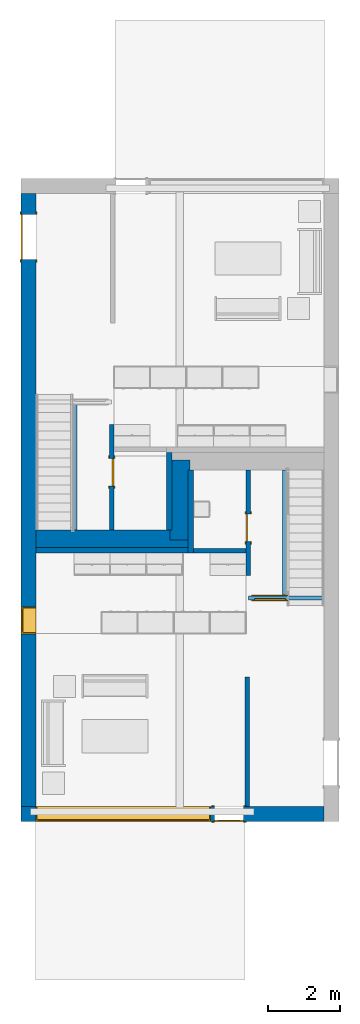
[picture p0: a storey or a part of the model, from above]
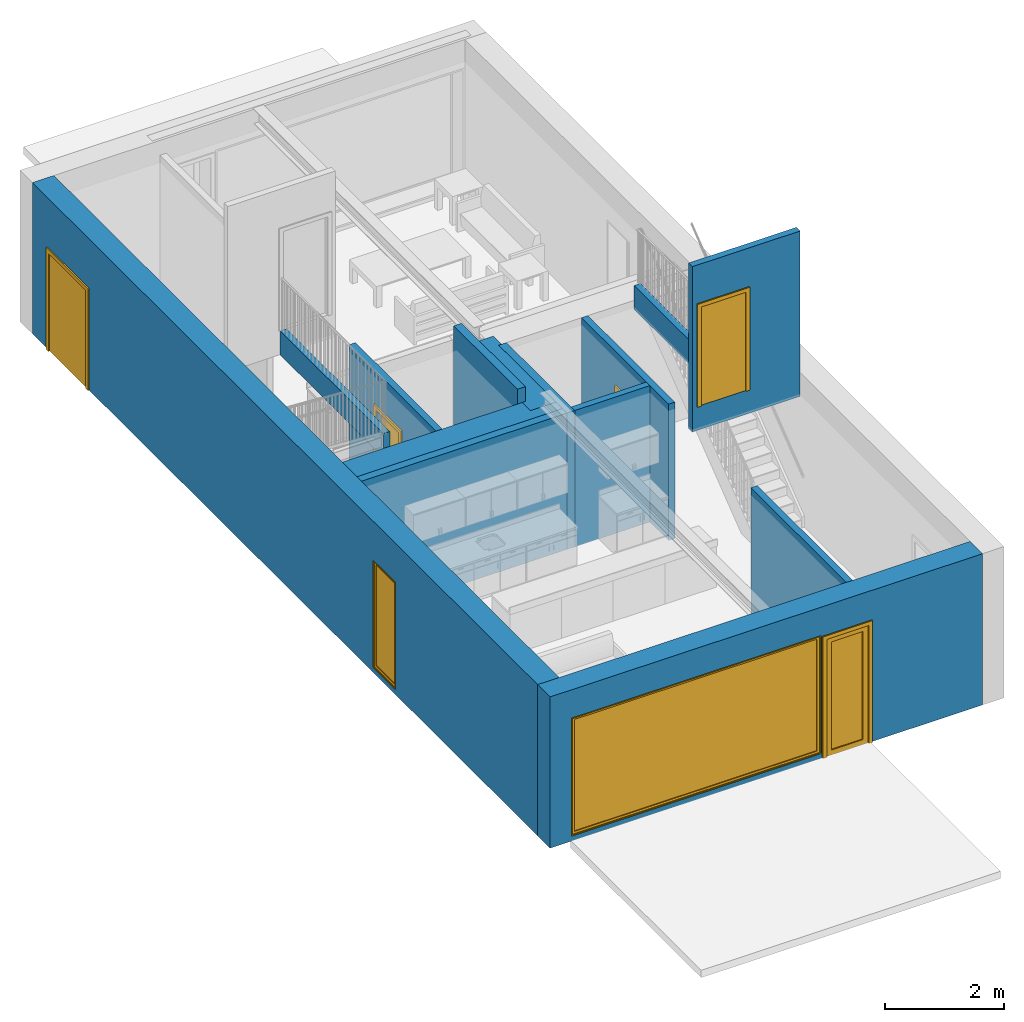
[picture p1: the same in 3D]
Properties of the parts of a building model (IFC4), part 1 of 3

# File
Description: ViewDefinition [DesignTransferView]
File name: Duplex_Apartment_IFC4_handover.ifc
Time: 2026-06-14T09:30:00
Written by: IfcOpenShell 0.8.5-1c5b825
Made in: IfcOpenShell 0.8.5-1c5b825

# IfcProject, 0001
LongName: Duplex Apartment; Phase: Project Status

# IfcSite, Default
RefLatitude: 41, 52, 27, 840000; RefLongitude: -87, -38, -21, -839999; RefElevation: 0 m

# IfcBuilding
PSet_Revit_Other - Project Issue Date: Issue Date; Project Status: Project Status; Client Name: Owner; Project Address: Enter address here; Project Name: Duplex Apartment; Project Number: 0001; Category Description: Duplex; Category Code: 11-16 21 11
Pset_BuildingCommon - NumberOfStoreys: 4

# IfcBuildingStorey (4)
PSet_Revit_Type_Graphics - Line Weight: 1; Color: 0; Line Pattern: Centre; Symbol: M_Level Head - Circle; Symbol at End 1 Default: no; Symbol at End 2 Default: yes
PSet_Revit_Type_Constraints - Elevation Base: 0
PSet_Revit_Type_Dimensions - Automatic Room Computation Height: yes
Name | Elevation (m) = PSet_Revit_Constraints, Elevation (m) | Name | Category Code
Level 1 | 0 | Level 1 | Floor
Level 2 | 3.1 | Level 2 | Floor
T/FDN | -1.25 | T/FDN | Site
Roof | 6 | Roof | Roof

# IfcSpace (21)
PredefinedType: SPACE
Pset_SpaceCommon - CeilingCovering: CeilingCovering; WallCovering: WallCovering; FloorCovering: FloorCovering
PSet_Revit_Constraints - Base Offset: 0 m
PSet_Revit_Phasing - Phase: New Construction
PSet_Revit_Other - CeilingCovering: CeilingCovering; FloorCovering: FloorCovering; WallCovering: WallCovering; LoadCapacity: LoadCapacity; RoomTag: RoomTag
Name | In | LongName = Name | Number | OmniClass Table 13 Category | Level | Upper Limit | Limit Offset (m) | Area (m2) = GSA BIM Area (m2) | Perimeter (m) | Unbounded Height (m) | Volume (m3) | Category Description | Category Code | CirculationZoneName | FireAlarmZoneName | HistoricPreservationZoneName | LightingZoneName | OccupancyZoneName | VentilationZoneName
B105 | Level 1 | Room | B105 | 13-85 21 11: Stairway | Level 1 | Level 2 | 2.6 | 4.92217 | 10.4958 | 5.7 | 20.7961 | Stairway | 13-85 21 11 | Unit B CirculationZoneName | Unit B FireAlarmZoneName | Unit B HistoricPreservationZoneName | Unit B LightingZoneName | Unit B OccupancyZoneName | Unit B VentilationZoneName
R301 | Roof | Roof | R301 | 13-81 11 99: Other General Facility Service Spaces | Roof | Roof | 3 | 145.722 | 51.532 | 3 | 405.453 | Other General Facility Service Spaces | 13-81 11 99 | Roof CirculationZoneName | Roof FireAlarmZoneName | Roof HistoricPreservationZoneName | Roof LightingZoneName | Roof OccupancyZoneName | Roof VentilationZoneName
B204 | Level 2 | Bathroom 2 | B204 | 13-41 11 14 11: Bathroom | Level 2 | Level 2 | 2.6 | 5.44147 | 9.8721 | 2.6 | 12.3011 | Bathroom | 13-41 11 14 11 | Unit B CirculationZoneName | Unit B FireAlarmZoneName | Unit B HistoricPreservationZoneName | Unit B LightingZoneName | Unit B OccupancyZoneName | Unit B VentilationZoneName
B203 | Level 2 | Bedroom 2 | B203 | 13-51 21 11: Bedroom | Level 2 | Level 2 | 2.6 | 26.178 | 21.908 | 2.6 | 56.8936 | Bedroom | 13-51 21 11 | Unit B CirculationZoneName | Unit B FireAlarmZoneName | Unit B HistoricPreservationZoneName | Unit B LightingZoneName | Unit B OccupancyZoneName | Unit B VentilationZoneName
B202 | Level 2 | Bedroom 1 | B202 | 13-51 21 11: Bedroom | Level 2 | Level 2 | 2.6 | 26.1193 | 21.422 | 2.6 | 56.8936 | Bedroom | 13-51 21 11 | Unit B CirculationZoneName | Unit B FireAlarmZoneName | Unit B HistoricPreservationZoneName | Unit B LightingZoneName | Unit B OccupancyZoneName | Unit B VentilationZoneName
A205 | Level 2 | Utility | A205 | 13-81 31: Service Distribution Spaces | Level 2 | Level 2 | 2.6 | 1.75405 | 5.43477 | 2.6 | 3.67206 | Service Distribution Spaces | 13-81 31 | Unit A CirculationZoneName | Unit A FireAlarmZoneName | Unit A HistoricPreservationZoneName | Unit A LightingZoneName | Unit A OccupancyZoneName | Unit A VentilationZoneName
B205 | Level 2 | Utility | B205 | 13-81 31: Service Distribution Spaces | Level 2 | Level 2 | 2.6 | 1.72839 | 5.4039 | 2.6 | 3.61121 | Service Distribution Spaces | 13-81 31 | Unit B CirculationZoneName | Unit B FireAlarmZoneName | Unit B HistoricPreservationZoneName | Unit B LightingZoneName | Unit B OccupancyZoneName | Unit B VentilationZoneName
A105 | Level 1 | Stair | A105 | 13-85 21 11: Stairway | Level 1 | Level 2 | 2.6 | 4.92217 | 10.4958 | 5.7 | 20.7961 | Stairway | 13-85 21 11 | Unit A CirculationZoneName | Unit A FireAlarmZoneName | Unit A HistoricPreservationZoneName | Unit A LightingZoneName | Unit A OccupancyZoneName | Unit A VentilationZoneName
A202 | Level 2 | Bedroom 1 | A202 | 13-51 21 11: Bedroom | Level 2 | Level 2 | 2.6 | 26.1193 | 21.422 | 2.6 | 56.8936 | Bedroom | 13-51 21 11 | Unit A CirculationZoneName | Unit A FireAlarmZoneName | Unit A HistoricPreservationZoneName | Unit A LightingZoneName | Unit A OccupancyZoneName | Unit A VentilationZoneName
B102 | Level 1 | Living Room | B102 | 13-51 24: Living Spaces | Level 1 | Level 1 | 2.6 | 30.1416 | 22.028 | 2.6 | 71.3907 | Living Spaces | 13-51 24 | Unit B CirculationZoneName | Unit B FireAlarmZoneName | Unit B HistoricPreservationZoneName | Unit B LightingZoneName | Unit B OccupancyZoneName | Unit B VentilationZoneName
B103 | Level 1 | Kitchen | B103 | 13-11 19 11 11: Kitchen | Level 1 | Level 1 | 2.6 | 13.8975 | 16.4195 | 2.6 | 33.5122 | Kitchen | 13-11 19 11 11 | Unit B CirculationZoneName | Unit B FireAlarmZoneName | Unit B HistoricPreservationZoneName | Unit B LightingZoneName | Unit B OccupancyZoneName | Unit B VentilationZoneName
B104 | Level 1 | Bathroom 1 | B104 | 13-41 11 14 11: Bathroom | Level 1 | Level 1 | 2.6 | 3.99775 | 8.204 | 2.6 | 8.17744 | Bathroom | 13-41 11 14 11 | Unit B CirculationZoneName | Unit B FireAlarmZoneName | Unit B HistoricPreservationZoneName | Unit B LightingZoneName | Unit B OccupancyZoneName | Unit B VentilationZoneName
B101 | Level 1 | Foyer | B101 | 13-51 24 11: General Residential Space | Level 1 | Level 1 | 2.6 | 17.9362 | 24.216 | 2.6 | 40.2413 | General Residential Space | 13-51 24 11 | Unit B CirculationZoneName | Unit B FireAlarmZoneName | Unit B HistoricPreservationZoneName | Unit B LightingZoneName | Unit B OccupancyZoneName | Unit B VentilationZoneName
B201 | Level 2 | Hallway | B201 | 13-51 24 11: General Residential Space | Level 2 | Roof | 0 | 7.79995 | 15.319 | 2.9 | 18.1155 | General Residential Space | 13-51 24 11 | Unit B CirculationZoneName | Unit B FireAlarmZoneName | Unit B HistoricPreservationZoneName | Unit B LightingZoneName | Unit B OccupancyZoneName | Unit B VentilationZoneName
A101 | Level 1 | Foyer | A101 | 13-51 24 11: General Residential Space | Level 1 | Level 1 | 2.6 | 17.9362 | 24.216 | 2.6 | 40.2413 | General Residential Space | 13-51 24 11 | Unit A CirculationZoneName | Unit A FireAlarmZoneName | Unit A HistoricPreservationZoneName | Unit A LightingZoneName | Unit A OccupancyZoneName | Unit A VentilationZoneName
A201 | Level 2 | Hallway | A201 | 13-51 24 11: General Residential Space | Level 2 | Roof | 0 | 7.79995 | 15.319 | 2.9 | 18.1155 | General Residential Space | 13-51 24 11 | Unit A CirculationZoneName | Unit A FireAlarmZoneName | Unit A HistoricPreservationZoneName | Unit A LightingZoneName | Unit A OccupancyZoneName | Unit A VentilationZoneName
A204 | Level 2 | Bathroom 2 | A204 | 13-41 11 14 11: Bathroom | Level 2 | Level 2 | 2.6 | 5.41582 | 9.84123 | 2.6 | 12.2402 | Bathroom | 13-41 11 14 11 | Unit A CirculationZoneName | Unit A FireAlarmZoneName | Unit A HistoricPreservationZoneName | Unit A LightingZoneName | Unit A OccupancyZoneName | Unit A VentilationZoneName
A203 | Level 2 | Bedroom 2 | A203 | 13-51 21 11: Bedroom | Level 2 | Level 2 | 2.6 | 26.178 | 21.482 | 2.6 | 56.8936 | Bedroom | 13-51 21 11 | Unit A CirculationZoneName | Unit A FireAlarmZoneName | Unit A HistoricPreservationZoneName | Unit A LightingZoneName | Unit A OccupancyZoneName | Unit A VentilationZoneName
A102 | Level 1 | Living Room | A102 | 13-51 24: Living Spaces | Level 1 | Level 1 | 2.6 | 30.1416 | 22.028 | 2.6 | 71.3907 | Living Spaces | 13-51 24 | Unit A CirculationZoneName | Unit A FireAlarmZoneName | Unit A HistoricPreservationZoneName | Unit A LightingZoneName | Unit A OccupancyZoneName | Unit A VentilationZoneName
A103 | Level 1 | Kitchen | A103 | 13-11 19 11 11: Kitchen | Level 1 | Level 1 | 2.6 | 13.8975 | 16.4195 | 2.6 | 33.5122 | Kitchen | 13-11 19 11 11 | Unit A CirculationZoneName | Unit A FireAlarmZoneName | Unit A HistoricPreservationZoneName | Unit A LightingZoneName | Unit A OccupancyZoneName | Unit A VentilationZoneName
A104 | Level 1 | Bathroom 1 | A104 | 13-41 11 14 11: Bathroom | Level 1 | Level 1 | 2.6 | 3.99775 | 8.204 | 2.6 | 8.17744 | Bathroom | 13-41 11 14 11 | Unit A CirculationZoneName | Unit A FireAlarmZoneName | Unit A HistoricPreservationZoneName | Unit A LightingZoneName | Unit A OccupancyZoneName | Unit A VentilationZoneName

# IfcBeam: M_W-Wide Flange:W310X60:208816 (2)
In: Level 1
Material: Metal - Steel - 345 MPa
PSet_Revit_Type_Structural - W: 0.58; A: 0.00753 m2
PSet_Revit_Type_Identity Data - Manufacturer: Manufacturer; OmniClass Number: 23.25.30.11.14.14; OmniClass Title: Beams
PSet_Revit_Type_Dimensions - bf: 0.203 m; d: 0.303 m; k: 0.033 m; kr: 0.0199 m; tf: 0.0131 m; tw: 0.0075 m
PSet_Revit_Type_Other - AccessibilityPerformance: AccessibilityPerformance; CodePerformance: CodePerformance; Color: Color; Constituents: Constituents; Features: Features; Finish: Finish; Grade: Grade; Material: Material; ModelReference: ModelReference; NominalHeight: NominalHeight; NominalLength: NominalLength; NominalWidth: NominalWidth; ProductionYear: ProductionYear; Reference: Reference; Shape: Shape; Size: Size; SustainabilityPerformance: SustainabilityPerformance; WarrantyDescription: WarrantyDescription; WarrantyDurationLabor: WarrantyDurationLabor; WarrantyDurationParts: WarrantyDurationParts; WarrantyGuarantorLabor: WarrantyGuarantorLabor; WarrantyGuarantorParts: WarrantyGuarantorParts; ExpectedLife: ExpectedLife; ReplacementCost: ReplacementCost; AssetAccountingType: FIXED; ModelLabel: ModelLabel
PSet_Revit_Constraints - Reference Level: Level 2; Work Plane: Level : Level 2; Start Level Offset: 0 m; End Level Offset: 0 m; z-Direction Justification: 0; z-Direction Offset Value: 0 m; Lateral Justification: 0; Orientation: 0; Cross-Section Rotation: 0 deg
PSet_Revit_Phasing - Phase Created: New Construction
PSet_Revit_Other - Start Extension Calculation: 3 m; End Extension Calculation: 3 m; InstallationDate: InstallationDate; SerialNumber: SerialNumber; WarrantyStartDate: WarrantyStartDate; BarCode: BarCode; AssetIdentifier: AssetIdentifier; TagNumber: TagNumber
PSet_Revit_Construction - Start Extension: -0.0127 m; End Extension: -0.0127 m
PSet_Revit_Materials and Finishes - Beam Material: Metal - Steel - 345 MPa
PSet_Revit_Dimensions - Length: 7.523 m; Volume: 0.0548775 m3
PSet_Revit_Structural - Stick Symbol Location: 0; Cut Length: 7.4213 m; Structural Usage: 3
PSet_Revit_Structural Analysis - Start Release: 3; Start Fx: no; Start Fy: no; Start Fz: no; Start Mx: no; Start My: yes; Start Mz: yes; End Release: 1; End Fx: no; End Fy: no; End Fz: no; End Mx: yes; End My: yes; End Mz: yes; Analyze As: 1
PSet_Revit_Analytical Model - Rigid Links: 0; Horizontal Projection: Default
Pset_BeamCommon - Reference: M_W-Wide Flange:W310X60; IsExternal: no; LoadBearing: yes; Span: 7.4213 m; Slope: 0 deg
Name (M_W-Wide Flange:W310X60:W310X60:...)
207325
209260

# IfcBeam: M_W-Wide Flange:W410X60:208814 (6)
Material: Metal - Steel - 345 MPa
PSet_Revit_Type_Structural - W: 0.58; A: 0.0076 m2
PSet_Revit_Type_Identity Data - Manufacturer: Manufacturer; OmniClass Number: 23.25.30.11.14.14; OmniClass Title: Beams
PSet_Revit_Type_Dimensions - bf: 0.178 m; d: 0.407 m; k: 0.03 m; kr: 0.0172 m; tf: 0.0128 m; tw: 0.0077 m
PSet_Revit_Type_Other - AccessibilityPerformance: AccessibilityPerformance; CodePerformance: CodePerformance; Color: Color; Constituents: Constituents; Features: Features; Finish: Finish; Grade: Grade; Material: Material; ModelReference: ModelReference; NominalHeight: NominalHeight; NominalLength: NominalLength; NominalWidth: NominalWidth; ProductionYear: ProductionYear; Reference: Reference; Shape: Shape; Size: Size; SustainabilityPerformance: SustainabilityPerformance; WarrantyDescription: WarrantyDescription; WarrantyDurationLabor: WarrantyDurationLabor; WarrantyDurationParts: WarrantyDurationParts; WarrantyGuarantorLabor: WarrantyGuarantorLabor; WarrantyGuarantorParts: WarrantyGuarantorParts; ExpectedLife: ExpectedLife; ReplacementCost: ReplacementCost; AssetAccountingType: FIXED; ModelLabel: ModelLabel
PSet_Revit_Other - Start Extension Calculation: 3 m; End Extension Calculation: 3 m; InstallationDate: InstallationDate; SerialNumber: SerialNumber; WarrantyStartDate: WarrantyStartDate; BarCode: BarCode; AssetIdentifier: AssetIdentifier; TagNumber: TagNumber
PSet_Revit_Construction - Start Extension: -0.0127 m; End Extension: -0.0127 m
PSet_Revit_Materials and Finishes - Beam Material: Metal - Steel - 345 MPa
PSet_Revit_Structural - Stick Symbol Location: 0; Structural Usage: 6
PSet_Revit_Structural Analysis - Start Release: 3; Start Fx: no; Start Fy: no; Start Fz: no; Start Mx: no; Start My: yes; Start Mz: yes; End Release: 1; End Fx: no; End Fy: no; End Fz: no; End Mx: yes; End My: yes; End Mz: yes; Analyze As: 1
PSet_Revit_Analytical Model - Rigid Links: 0; Horizontal Projection: Default
PSet_Revit_Constraints - Start Level Offset: 0 m; End Level Offset: 0 m; z-Direction Justification: 0; z-Direction Offset Value: 0 m; Lateral Justification: 0; Orientation: 0; Cross-Section Rotation: 0 deg
PSet_Revit_Phasing - Phase Created: New Construction
Pset_BeamCommon - Reference: M_W-Wide Flange:W410X60; IsExternal: no; LoadBearing: yes; Slope: 0 deg
Name (M_W-Wide Flange:W410X60:W410X60:...) | In | Length (m) = Cut Length (m) = Span (m) | Volume (m3) | Reference Level | Work Plane
208949 | Level 1 | 6.18189 | 0.0463245 | Level 2 | Level : Level 2
209121 | Level 2 | 4.12128 | 0.0308831 | Roof | Level : Roof
209166 | Level 2 | 4.1 | 0.0307237 | Roof | Level : Roof
209261 | Level 1 | 6.18189 | 0.0463245 | Level 2 | Level : Level 2
209262 | Level 2 | 4.12128 | 0.0308831 | Roof | Level : Roof
209263 | Level 2 | 4.1 | 0.0307237 | Roof | Level : Roof

# IfcCovering: Compound Ceiling:Gypsum Board (13)
PredefinedType: CEILING; Material: Metal - Stud Layer 0.045 m, Plasterboard 0.012 m
PSet_Revit_Type_Construction - Thickness: 0.057 m
PSet_Revit_Type_Graphics - Coarse Scale Fill Color: 0
PSet_Revit_Type_Identity Data - Manufacturer: Manufacturer
PSet_Revit_Type_Other - AccessibilityPerformance: AccessibilityPerformance; CodePerformance: CodePerformance; Color: Color; Constituents: Constituents; Features: Features; Finish: Finish; Grade: Grade; Material: Material; ModelReference: ModelReference; NominalHeight: NominalHeight; NominalLength: NominalLength; NominalWidth: NominalWidth; ProductionYear: ProductionYear; Reference: Reference; Shape: Shape; Size: Size; SustainabilityPerformance: SustainabilityPerformance; WarrantyDescription: WarrantyDescription; WarrantyDurationLabor: WarrantyDurationLabor; WarrantyDurationParts: WarrantyDurationParts; WarrantyGuarantorLabor: WarrantyGuarantorLabor; WarrantyGuarantorParts: WarrantyGuarantorParts; ExpectedLife: ExpectedLife; ReplacementCost: ReplacementCost; AssetAccountingType: FIXED; Classification Description: Ceilings; Classification Code: 23-35 70 24; ModelLabel: ModelLabel
Pset_CoveringCommon - Reference: Compound Ceiling:Gypsum Board; TotalThickness: 0.057 m
PSet_Revit_Constraints - Height Offset From Level: 2.6 m; Room Bounding: yes
PSet_Revit_Other - InstallationDate: InstallationDate; SerialNumber: SerialNumber; WarrantyStartDate: WarrantyStartDate; BarCode: BarCode; AssetIdentifier: AssetIdentifier; TagNumber: TagNumber
PSet_Revit_Phasing - Phase Created: New Construction
Name (Compound Ceiling:Gypsum Board:...) | In | Level | Perimeter (m) | Area (m2) | Volume (m3)
187683 | Level 2 | Level 2 | 18.7504 | 9.30194 | 0.530211
187149 | Level 1 | Level 1 | 42.924 | 57.0343 | 3.25096
187639 | Level 2 | Level 2 | 19.914 | 22.0432 | 1.25646
187691 | Level 2 | Level 2 | 19.914 | 22.0432 | 1.25646
187659 | Level 2 | Level 2 | 11.558 | 6.73504 | 0.383897
187675 | Level 2 | Level 2 | 11.558 | 6.73504 | 0.383897
187667 | Level 2 | Level 2 | 18.7504 | 9.30194 | 0.530211
187508 | Level 1 | Level 1 | 42.574 | 56.4575 | 3.21808
187462 | Level 1 | Level 1 | 7.198 | 3.17645 | 0.181058
187470 | Level 1 | Level 1 | 7.198 | 3.17645 | 0.181058
187701 | Level 2 | Level 2 | 19.914 | 22.0432 | 1.25646
187649 | Level 2 | Level 2 | 19.914 | 22.0432 | 1.25646
187483 | Level 1 | Level 1 | 7.444 | 3.36722 | 0.191932

# IfcDoor: 0762 x 2032mm (2)
In: Level 1
Type - PredefinedType: DOOR; OperationType: SINGLE_SWING_LEFT; ParameterTakesPrecedence: no
OverallHeight: 2.032 m; OverallWidth: 0.762 m
PSet_Revit_Type_Dimensions - Thickness: 0.051 m; Height: 2.032 m; Trim Projection Ext: 0.025 m; Trim Projection Int: 0.025 m; Trim Width: 0.076 m; Width: 0.762 m
PSet_Revit_Type_Construction - Function: 0; Wall Closure: 0; Construction Type: Construction Type
PSet_Revit_Type_Materials and Finishes - Door Material: Door - Panel; Frame Material: Door - Frame
PSet_Revit_Type_Identity Data - Manufacturer: Manufacturer; Type Mark: 28; Fire Rating: Fire Rating; OmniClass Number: 23.30.10.00; OmniClass Title: Doors
PSet_Revit_Type_Other - AccessibilityPerformance: AccessibilityPerformance; CodePerformance: CodePerformance; IsFireExit: IsFireExit; ConstructionType: ConstructionType; GlazingAreaFraction: GlazingAreaFraction; OperationType: OperationType; Area: Area; Color: Color; Constituents: Constituents; Features: Features; Finish: Finish; Grade: Grade; Material: Material; ModelReference: ModelReference; NominalHeight: NominalHeight; NominalLength: NominalLength; NominalWidth: NominalWidth; ProductionYear: ProductionYear; Reference: Reference; Shape: Shape; Size: Size; SustainabilityPerformance: SustainabilityPerformance; WarrantyDescription: WarrantyDescription; WarrantyDurationLabor: WarrantyDurationLabor; WarrantyDurationParts: WarrantyDurationParts; WarrantyGuarantorLabor: WarrantyGuarantorLabor; WarrantyGuarantorParts: WarrantyGuarantorParts; ExpectedLife: ExpectedLife; ReplacementCost: ReplacementCost; AssetAccountingType: FIXED; ModelLabel: ModelLabel
Pset_DoorCommon - Reference: M_Single-Flush:0762 x 2032mm; IsExternal: no; FireRating: Fire Rating
PSet_Revit_Constraints - Level: Level 1; Sill Height: 0 m
PSet_Revit_Other - Head Height: 2.032 m; InstallationDate: InstallationDate; SerialNumber: SerialNumber; WarrantyStartDate: WarrantyStartDate; BarCode: BarCode; AssetIdentifier: AssetIdentifier; TagNumber: TagNumber
PSet_Revit_Phasing - Phase Created: New Construction
Name (M_Single-Flush:0762 x 2032mm:0762 x 2032mm:...) | Mark
150257 | B104
150173 | A104

# IfcDoor: 0762 x 2032mm (2)
In: Level 2
Type - PredefinedType: DOOR; OperationType: SINGLE_SWING_RIGHT; ParameterTakesPrecedence: no
OverallHeight: 2.032 m; OverallWidth: 0.762 m
PSet_Revit_Type_Dimensions - Thickness: 0.051 m; Height: 2.032 m; Trim Projection Ext: 0.025 m; Trim Projection Int: 0.025 m; Trim Width: 0.076 m; Width: 0.762 m
PSet_Revit_Type_Construction - Function: 0; Wall Closure: 0; Construction Type: Construction Type
PSet_Revit_Type_Materials and Finishes - Door Material: Door - Panel; Frame Material: Door - Frame
PSet_Revit_Type_Identity Data - Manufacturer: Manufacturer; Type Mark: 28; Fire Rating: Fire Rating; OmniClass Number: 23.30.10.00; OmniClass Title: Doors
PSet_Revit_Type_Other - AccessibilityPerformance: AccessibilityPerformance; CodePerformance: CodePerformance; IsFireExit: IsFireExit; ConstructionType: ConstructionType; GlazingAreaFraction: GlazingAreaFraction; OperationType: OperationType; Area: Area; Color: Color; Constituents: Constituents; Features: Features; Finish: Finish; Grade: Grade; Material: Material; ModelReference: ModelReference; NominalHeight: NominalHeight; NominalLength: NominalLength; NominalWidth: NominalWidth; ProductionYear: ProductionYear; Reference: Reference; Shape: Shape; Size: Size; SustainabilityPerformance: SustainabilityPerformance; WarrantyDescription: WarrantyDescription; WarrantyDurationLabor: WarrantyDurationLabor; WarrantyDurationParts: WarrantyDurationParts; WarrantyGuarantorLabor: WarrantyGuarantorLabor; WarrantyGuarantorParts: WarrantyGuarantorParts; ExpectedLife: ExpectedLife; ReplacementCost: ReplacementCost; AssetAccountingType: FIXED; ModelLabel: ModelLabel
PSet_Revit_Constraints - Level: Level 2; Sill Height: 0 m
PSet_Revit_Other - Head Height: 2.032 m; InstallationDate: InstallationDate; SerialNumber: SerialNumber; WarrantyStartDate: WarrantyStartDate; BarCode: BarCode; AssetIdentifier: AssetIdentifier; TagNumber: TagNumber
PSet_Revit_Phasing - Phase Created: New Construction
Pset_DoorCommon - Reference: M_Single-Flush:0762 x 2032mm; IsExternal: no; FireRating: Fire Rating
Name (M_Single-Flush:0762 x 2032mm:0762 x 2032mm:...) | Mark
203720 | B205
204034 | A205

# IfcDoor: 0813 x 2420mm (2)
In: Level 1
Type - PredefinedType: DOOR; OperationType: SINGLE_SWING_LEFT; ParameterTakesPrecedence: no
OverallHeight: 2.42 m; OverallWidth: 0.813 m
PSet_Revit_Type_Materials and Finishes - Door Material: Door - Panel; Frame Material: Door - Frame
PSet_Revit_Type_Identity Data - Manufacturer: Manufacturer; Type Mark: 56; Fire Rating: Fire Rating; OmniClass Number: 23.30.10.00; OmniClass Title: Doors
PSet_Revit_Type_Other - AccessibilityPerformance: AccessibilityPerformance; CodePerformance: CodePerformance; IsFireExit: IsFireExit; ConstructionType: ConstructionType; GlazingAreaFraction: GlazingAreaFraction; OperationType: OperationType; Area: Area; Color: Color; Constituents: Constituents; Features: Features; Finish: Finish; Grade: Grade; Material: Material; ModelReference: ModelReference; NominalHeight: NominalHeight; NominalLength: NominalLength; NominalWidth: NominalWidth; ProductionYear: ProductionYear; Reference: Reference; Shape: Shape; Size: Size; SustainabilityPerformance: SustainabilityPerformance; WarrantyDescription: WarrantyDescription; WarrantyDurationLabor: WarrantyDurationLabor; WarrantyDurationParts: WarrantyDurationParts; WarrantyGuarantorLabor: WarrantyGuarantorLabor; WarrantyGuarantorParts: WarrantyGuarantorParts; ExpectedLife: ExpectedLife; ReplacementCost: ReplacementCost; AssetAccountingType: FIXED; ModelLabel: ModelLabel
PSet_Revit_Type_Dimensions - Thickness: 0.051 m; Height: 2.42 m; Rail Width - Base: 0.102 m; Rail Width - Top: 0.102 m; Stile Width - Hinge: 0.102 m; Stile Width - Latch: 0.102 m; Trim Projection Ext: 0.025 m; Trim Projection Int: 0.025 m; Trim Width: 0.076 m; Width: 0.813 m
PSet_Revit_Type_Construction - Function: 1; Wall Closure: 0; Construction Type: Construction Type
PSet_Revit_Constraints - Level: Level 1; Sill Height: 0 m
PSet_Revit_Other - Head Height: 2.42 m; InstallationDate: InstallationDate; SerialNumber: SerialNumber; WarrantyStartDate: WarrantyStartDate; BarCode: BarCode; AssetIdentifier: AssetIdentifier; TagNumber: TagNumber
PSet_Revit_Phasing - Phase Created: New Construction
Pset_DoorCommon - Reference: M_Single-Glass 1:0813 x 2420mm; IsExternal: yes; FireRating: Fire Rating
Name (M_Single-Glass 1:0813 x 2420mm:0813 x 2420mm:...) | Mark
171853 | B102
171975 | A102

# IfcDoor: 0864 x 2032mm (2)
In: Level 2
Type - PredefinedType: DOOR; OperationType: SINGLE_SWING_LEFT; ParameterTakesPrecedence: no
OverallHeight: 2.032 m; OverallWidth: 0.864 m
PSet_Revit_Type_Dimensions - Thickness: 0.051 m; Height: 2.032 m; Trim Projection Ext: 0.025 m; Trim Projection Int: 0.025 m; Trim Width: 0.076 m; Width: 0.864 m
PSet_Revit_Type_Construction - Function: 0; Wall Closure: 0; Construction Type: Construction Type
PSet_Revit_Type_Materials and Finishes - Door Material: Door - Panel; Frame Material: Door - Frame
PSet_Revit_Type_Identity Data - Manufacturer: Manufacturer; Type Mark: 32; Fire Rating: Fire Rating; OmniClass Number: 23.30.10.00; OmniClass Title: Doors
PSet_Revit_Type_Other - AccessibilityPerformance: AccessibilityPerformance; CodePerformance: CodePerformance; IsFireExit: IsFireExit; ConstructionType: ConstructionType; GlazingAreaFraction: GlazingAreaFraction; OperationType: OperationType; Area: Area; Color: Color; Constituents: Constituents; Features: Features; Finish: Finish; Grade: Grade; Material: Material; ModelReference: ModelReference; NominalHeight: NominalHeight; NominalLength: NominalLength; NominalWidth: NominalWidth; ProductionYear: ProductionYear; Reference: Reference; Shape: Shape; Size: Size; SustainabilityPerformance: SustainabilityPerformance; WarrantyDescription: WarrantyDescription; WarrantyDurationLabor: WarrantyDurationLabor; WarrantyDurationParts: WarrantyDurationParts; WarrantyGuarantorLabor: WarrantyGuarantorLabor; WarrantyGuarantorParts: WarrantyGuarantorParts; ExpectedLife: ExpectedLife; ReplacementCost: ReplacementCost; AssetAccountingType: FIXED; ModelLabel: ModelLabel
Pset_DoorCommon - Reference: M_Single-Flush:0864 x 2032mm; IsExternal: no; FireRating: Fire Rating
PSet_Revit_Constraints - Level: Level 2; Sill Height: 0 m
PSet_Revit_Other - Head Height: 2.032 m; InstallationDate: InstallationDate; SerialNumber: SerialNumber; WarrantyStartDate: WarrantyStartDate; BarCode: BarCode; AssetIdentifier: AssetIdentifier; TagNumber: TagNumber
PSet_Revit_Phasing - Phase Created: New Construction
Name (M_Single-Flush:0864 x 2032mm:0864 x 2032mm:...) | Mark
159734 | B202
159834 | A202

# IfcDoor: 0864 x 2032mm (4)
In: Level 2
Type - PredefinedType: DOOR; OperationType: SINGLE_SWING_RIGHT; ParameterTakesPrecedence: no
OverallHeight: 2.032 m; OverallWidth: 0.864 m
PSet_Revit_Type_Dimensions - Thickness: 0.051 m; Height: 2.032 m; Trim Projection Ext: 0.025 m; Trim Projection Int: 0.025 m; Trim Width: 0.076 m; Width: 0.864 m
PSet_Revit_Type_Construction - Function: 0; Wall Closure: 0; Construction Type: Construction Type
PSet_Revit_Type_Materials and Finishes - Door Material: Door - Panel; Frame Material: Door - Frame
PSet_Revit_Type_Identity Data - Manufacturer: Manufacturer; Type Mark: 32; Fire Rating: Fire Rating; OmniClass Number: 23.30.10.00; OmniClass Title: Doors
PSet_Revit_Type_Other - AccessibilityPerformance: AccessibilityPerformance; CodePerformance: CodePerformance; IsFireExit: IsFireExit; ConstructionType: ConstructionType; GlazingAreaFraction: GlazingAreaFraction; OperationType: OperationType; Area: Area; Color: Color; Constituents: Constituents; Features: Features; Finish: Finish; Grade: Grade; Material: Material; ModelReference: ModelReference; NominalHeight: NominalHeight; NominalLength: NominalLength; NominalWidth: NominalWidth; ProductionYear: ProductionYear; Reference: Reference; Shape: Shape; Size: Size; SustainabilityPerformance: SustainabilityPerformance; WarrantyDescription: WarrantyDescription; WarrantyDurationLabor: WarrantyDurationLabor; WarrantyDurationParts: WarrantyDurationParts; WarrantyGuarantorLabor: WarrantyGuarantorLabor; WarrantyGuarantorParts: WarrantyGuarantorParts; ExpectedLife: ExpectedLife; ReplacementCost: ReplacementCost; AssetAccountingType: FIXED; ModelLabel: ModelLabel
Pset_DoorCommon - Reference: M_Single-Flush:0864 x 2032mm; IsExternal: no; FireRating: Fire Rating
PSet_Revit_Constraints - Level: Level 2; Sill Height: 0 m
PSet_Revit_Other - Head Height: 2.032 m; InstallationDate: InstallationDate; SerialNumber: SerialNumber; WarrantyStartDate: WarrantyStartDate; BarCode: BarCode; AssetIdentifier: AssetIdentifier; TagNumber: TagNumber
PSet_Revit_Phasing - Phase Created: New Construction
Name (M_Single-Flush:0864 x 2032mm:0864 x 2032mm:...) | Mark
160065 | B204
150378 | B203
160208 | A204
150478 | A203

# IfcDoor: 1250mm x 2010mm (2)
In: Level 1
Type - PredefinedType: DOOR; OperationType: SINGLE_SWING_RIGHT; ParameterTakesPrecedence: no
OverallHeight: 2.01 m; OverallWidth: 1.25 m
PSet_Revit_Type_Dimensions - Thickness: 0.051 m; Height: 2.01 m; Trim Projection Ext: 0.025 m; Trim Projection Int: 0.025 m; Trim Width: 0.076 m; Width: 1.25 m
PSet_Revit_Type_Construction - Function: 1; Wall Closure: 0; Construction Type: Construction Type
PSet_Revit_Type_Materials and Finishes - Door Material: Door - Panel; Frame Material: Door - Frame
PSet_Revit_Type_Identity Data - Manufacturer: Manufacturer; Type Mark: 33; Fire Rating: Fire Rating; OmniClass Number: 23.30.10.00; OmniClass Title: Doors
PSet_Revit_Type_Other - AccessibilityPerformance: AccessibilityPerformance; CodePerformance: CodePerformance; IsFireExit: IsFireExit; ConstructionType: ConstructionType; GlazingAreaFraction: GlazingAreaFraction; OperationType: OperationType; Area: Area; Color: Color; Constituents: Constituents; Features: Features; Finish: Finish; Grade: Grade; Material: Material; ModelReference: ModelReference; NominalHeight: NominalHeight; NominalLength: NominalLength; NominalWidth: NominalWidth; ProductionYear: ProductionYear; Reference: Reference; Shape: Shape; Size: Size; SustainabilityPerformance: SustainabilityPerformance; WarrantyDescription: WarrantyDescription; WarrantyDurationLabor: WarrantyDurationLabor; WarrantyDurationParts: WarrantyDurationParts; WarrantyGuarantorLabor: WarrantyGuarantorLabor; WarrantyGuarantorParts: WarrantyGuarantorParts; ExpectedLife: ExpectedLife; ReplacementCost: ReplacementCost; AssetAccountingType: FIXED; ModelLabel: ModelLabel
Pset_DoorCommon - Reference: M_Single-Flush:1250mm x 2010mm; IsExternal: yes; FireRating: Fire Rating
PSet_Revit_Constraints - Level: Level 1; Sill Height: 0 m
PSet_Revit_Other - Head Height: 2.01 m; InstallationDate: InstallationDate; SerialNumber: SerialNumber; WarrantyStartDate: WarrantyStartDate; BarCode: BarCode; AssetIdentifier: AssetIdentifier; TagNumber: TagNumber
PSet_Revit_Phasing - Phase Created: New Construction
Name (M_Single-Flush:1250mm x 2010mm:1250mm x 2010mm:...) | Mark
146678 | B101
146596 | A101

# IfcFooting: Wall Foundation:Bearing Footing - 900 x 300 (7)
In: T/FDN
PredefinedType: STRIP_FOOTING
PSet_Revit_Type_Materials and Finishes - Material: Concrete - Cast In Situ
PSet_Revit_Type_Dimensions - Width: 0.9 m; Foundation Thickness: 0.3 m; Default End Extension Length: 0 m; Do Not Break At Inserts: no
PSet_Revit_Type_Structural - Structural Usage: 1
PSet_Revit_Type_Identity Data - Manufacturer: Manufacturer
PSet_Revit_Type_Other - AccessibilityPerformance: AccessibilityPerformance; CodePerformance: CodePerformance; Color: Color; Constituents: Constituents; Features: Features; Finish: Finish; Grade: Grade; Material: Material; ModelReference: ModelReference; NominalHeight: NominalHeight; NominalLength: NominalLength; NominalWidth: NominalWidth; ProductionYear: ProductionYear; Reference: Reference; Shape: Shape; Size: Size; SustainabilityPerformance: SustainabilityPerformance; WarrantyDescription: WarrantyDescription; WarrantyDurationLabor: WarrantyDurationLabor; WarrantyDurationParts: WarrantyDurationParts; WarrantyGuarantorLabor: WarrantyGuarantorLabor; WarrantyGuarantorParts: WarrantyGuarantorParts; ExpectedLife: ExpectedLife; ReplacementCost: ReplacementCost; AssetAccountingType: FIXED; Classification Description: Shallow Foundations; Classification Code: 23-25 05 17; ModelLabel: ModelLabel
PSet_Revit_Dimensions - Width: 0.9 m
PSet_Revit_Constraints - Eccentricity: 0 m
PSet_Revit_Other - InstallationDate: InstallationDate; SerialNumber: SerialNumber; WarrantyStartDate: WarrantyStartDate; BarCode: BarCode; AssetIdentifier: AssetIdentifier; TagNumber: TagNumber
PSet_Revit_Phasing - Phase Created: New Construction
PSet_Revit_Structural Analysis - Analyze As: 4
PSet_Revit_Structural - Rebar Cover - Top Face: Rebar Cover 1 <0.025>; Rebar Cover - Bottom Face: Rebar Cover 1 <0.025>; Rebar Cover - Other Faces: Rebar Cover 1 <0.025>
Name (Wall Foundation:Bearing Footing - 900 x 300:...) | Length (m) | Volume (m3)
186596 | 17.383 | 4.93641 | PSet_Revit_Dimensions - Elevation at Bottom: -1.55 m
186604 | 8.383 | 2.26341
186612 | 16.966 | 4.69341
186620 | 8.8 | 2.02041
186632 | 4.2005 | 1.1317
186644 | 1.765 | 0.594
186656 | 4.2005 | 0.888705

# IfcFurnishingElement: 0610 x 0610 x 0610mm (8)
Type - ElementType: 0610 x 0610 x 0610mm
PSet_Revit_Type_Materials and Finishes - Top Material: Metal - Chrome; Frame Material: Wood - Teak
PSet_Revit_Type_Dimensions - Height: 0.61 m; Length: 0.61 m; Width: 0.61 m
PSet_Revit_Type_Identity Data - Manufacturer: Manufacturer; OmniClass Number: 23.40.20.14.17.24; OmniClass Title: Coffee Tables
PSet_Revit_Type_Other - AccessibilityPerformance: AccessibilityPerformance; CodePerformance: CodePerformance; Area: Area; Color: Color; Constituents: Constituents; Features: Features; Finish: Finish; Grade: Grade; Material: Material; ModelReference: ModelReference; NominalHeight: NominalHeight; NominalLength: NominalLength; NominalWidth: NominalWidth; ProductionYear: ProductionYear; Reference: Reference; Shape: Shape; Size: Size; SustainabilityPerformance: SustainabilityPerformance; WarrantyDescription: WarrantyDescription; WarrantyDurationLabor: WarrantyDurationLabor; WarrantyDurationParts: WarrantyDurationParts; WarrantyGuarantorLabor: WarrantyGuarantorLabor; WarrantyGuarantorParts: WarrantyGuarantorParts; ExpectedLife: ExpectedLife; ReplacementCost: ReplacementCost; AssetAccountingType: NONFIXED; ModelLabel: ModelLabel
PSet_Revit_Constraints - Moves With Nearby Elements: no
PSet_Revit_Other - InstallationDate: InstallationDate; SerialNumber: SerialNumber; WarrantyStartDate: WarrantyStartDate; BarCode: BarCode; AssetIdentifier: AssetIdentifier; TagNumber: TagNumber
PSet_Revit_Phasing - Phase Created: New Construction
Name (M_Table-Coffee:0610 x 0610 x 0610mm:0610 x 0610 x 0610mm:...) | In | Level | Host
167584 | B102 | Level 1 | Floor : 127mm Slab on Grade
167655 | B102 | Level 1 | Floor : 127mm Slab on Grade
168379 | A102 | Level 1 | Floor : 127mm Slab on Grade
168380 | A102 | Level 1 | Floor : 127mm Slab on Grade
206283 | B203 | Level 2 | Floor : Finish Floor - Wood
206502 | A202 | Level 2 | Floor : Finish Floor - Wood
206675 | B202 | Level 2 | Floor : Finish Floor - Wood
206876 | A203 | Level 2 | Floor : Finish Floor - Wood

# IfcFurnishingElement: 0915 x 1830 x 0457mm (2)
Type - ElementType: 0915 x 1830 x 0457mm
PSet_Revit_Type_Materials and Finishes - Top Material: Metal - Chrome; Frame Material: Wood - Teak
PSet_Revit_Type_Dimensions - Height: 0.457 m; Length: 1.83 m; Width: 0.915 m
PSet_Revit_Type_Identity Data - Manufacturer: Manufacturer; OmniClass Number: 23.40.20.14.17.24; OmniClass Title: Coffee Tables
PSet_Revit_Type_Other - AccessibilityPerformance: AccessibilityPerformance; CodePerformance: CodePerformance; Area: Area; Color: Color; Constituents: Constituents; Features: Features; Finish: Finish; Grade: Grade; Material: Material; ModelReference: ModelReference; NominalHeight: NominalHeight; NominalLength: NominalLength; NominalWidth: NominalWidth; ProductionYear: ProductionYear; Reference: Reference; Shape: Shape; Size: Size; SustainabilityPerformance: SustainabilityPerformance; WarrantyDescription: WarrantyDescription; WarrantyDurationLabor: WarrantyDurationLabor; WarrantyDurationParts: WarrantyDurationParts; WarrantyGuarantorLabor: WarrantyGuarantorLabor; WarrantyGuarantorParts: WarrantyGuarantorParts; ExpectedLife: ExpectedLife; ReplacementCost: ReplacementCost; AssetAccountingType: NONFIXED; ModelLabel: ModelLabel
PSet_Revit_Constraints - Level: Level 1; Host: Floor : 127mm Slab on Grade; Moves With Nearby Elements: no
PSet_Revit_Other - InstallationDate: InstallationDate; SerialNumber: SerialNumber; WarrantyStartDate: WarrantyStartDate; BarCode: BarCode; AssetIdentifier: AssetIdentifier; TagNumber: TagNumber
PSet_Revit_Phasing - Phase Created: New Construction
Name (M_Table-Coffee:0915 x 1830 x 0457mm:0915 x 1830 x 0457mm:...) | In
168031 | B102
168381 | A102

# IfcFurnishingElement: 1000 mm (6)
Type - ElementType: 1000 mm
PSet_Revit_Type_Materials and Finishes - Handle Material: Cabinets - Handles; Finish: Finish
PSet_Revit_Type_Dimensions - Depth: 0.3 m; Height: 0.6 m; Top Of Cabinet: 2 m; Width: 1 m
PSet_Revit_Type_Identity Data - Manufacturer: Manufacturer; OmniClass Number: 23.40.35.17.47.11; OmniClass Title: Kitchen Casework
PSet_Revit_Type_Construction - Construction Type: Construction Type
PSet_Revit_Type_Other - AccessibilityPerformance: AccessibilityPerformance; CodePerformance: CodePerformance; Area: Area; Color: Color; Constituents: Constituents; Features: Features; Finish: Finish; Grade: Grade; Material: Material; ModelReference: ModelReference; NominalHeight: NominalHeight; NominalLength: NominalLength; NominalWidth: NominalWidth; ProductionYear: ProductionYear; Reference: Reference; Shape: Shape; Size: Size; SustainabilityPerformance: SustainabilityPerformance; WarrantyDescription: WarrantyDescription; WarrantyDurationLabor: WarrantyDurationLabor; WarrantyDurationParts: WarrantyDurationParts; WarrantyGuarantorLabor: WarrantyGuarantorLabor; WarrantyGuarantorParts: WarrantyGuarantorParts; ExpectedLife: ExpectedLife; ReplacementCost: ReplacementCost; AssetAccountingType: FIXED; ModelLabel: ModelLabel
PSet_Revit_Constraints - Level: Level 1; Elevation: 1.4 m
PSet_Revit_Other - InstallationDate: InstallationDate; SerialNumber: SerialNumber; WarrantyStartDate: WarrantyStartDate; BarCode: BarCode; AssetIdentifier: AssetIdentifier; TagNumber: TagNumber
PSet_Revit_Phasing - Phase Created: New Construction
Name (M_Upper Cabinet-Double Door-Wall:1000 mm:1000 mm:...) | In
191401 | A103
191557 | A103
191680 | A103
192153 | B103
192331 | B103
192508 | B103

# IfcFurnishingElement: 1000mm (18)
Type - ElementType: 1000mm
PSet_Revit_Type_Materials and Finishes - Handle Material: Cabinets - Handles; Finish: Finish
PSet_Revit_Type_Dimensions - Width: 1 m
PSet_Revit_Type_Identity Data - Manufacturer: Manufacturer; OmniClass Number: 23.40.35.17.47.11; OmniClass Title: Kitchen Casework
PSet_Revit_Type_Construction - Construction Type: Construction Type
PSet_Revit_Type_Other - AccessibilityPerformance: AccessibilityPerformance; CodePerformance: CodePerformance; Area: Area; Color: Color; Constituents: Constituents; Features: Features; Finish: Finish; Grade: Grade; Material: Material; ModelReference: ModelReference; NominalHeight: NominalHeight; NominalLength: NominalLength; NominalWidth: NominalWidth; ProductionYear: ProductionYear; Reference: Reference; Shape: Shape; Size: Size; SustainabilityPerformance: SustainabilityPerformance; WarrantyDescription: WarrantyDescription; WarrantyDurationLabor: WarrantyDurationLabor; WarrantyDurationParts: WarrantyDurationParts; WarrantyGuarantorLabor: WarrantyGuarantorLabor; WarrantyGuarantorParts: WarrantyGuarantorParts; ExpectedLife: ExpectedLife; ReplacementCost: ReplacementCost; AssetAccountingType: FIXED; ModelLabel: ModelLabel
PSet_Revit_Constraints - Level: Level 1
PSet_Revit_Other - InstallationDate: InstallationDate; SerialNumber: SerialNumber; WarrantyStartDate: WarrantyStartDate; BarCode: BarCode; AssetIdentifier: AssetIdentifier; TagNumber: TagNumber
PSet_Revit_Phasing - Phase Created: New Construction
Name | In | Depth (m) | Height (m) | Plinth Depth (m) | Plinth Height (m) | Host | Offset (m) | Moves With Nearby Elements
M_Base Cabinet-Double Door & 2 Drawer:1000mm:1000mm:159159 | B103 | 0.6 | 0.86 | 0.035 | 0.1 | Floor : 127mm Slab on Grade | 0 | no
M_Base Cabinet-Double Door & 2 Drawer:1000mm:1000mm:159262 | B103 | 0.6 | 0.86 | 0.035 | 0.1 | Floor : 127mm Slab on Grade | 0 | no
M_Base Cabinet-Double Door & 2 Drawer:1000mm:1000mm:160671 | B103 | 0.6 | 0.86 | 0.035 | 0.1 | Floor : 127mm Slab on Grade | 0 | no
M_Base Cabinet-Double Door & 2 Drawer:1000mm:1000mm:160717 | B103 | 0.6 | 0.86 | 0.035 | 0.1 | Floor : 127mm Slab on Grade | 0 | no
M_Base Cabinet-Double Door & 2 Drawer:1000mm:1000mm:162230 | B103 | 0.6 | 0.86 | 0.035 | 0.1 | Floor : 127mm Slab on Grade | 0 | no
M_Base Cabinet-Double Door & 2 Drawer:1000mm:1000mm:162311 | B103 | 0.6 | 0.86 | 0.035 | 0.1 | Floor : 127mm Slab on Grade | 0 | no
M_Base Cabinet-Double Door & 2 Drawer:1000mm:1000mm:162357 | B103 | 0.6 | 0.86 | 0.035 | 0.1 | Floor : 127mm Slab on Grade | 0 | no
M_Base Cabinet-Double Door & 2 Drawer:1000mm:1000mm:162383 | B103 | 0.6 | 0.86 | 0.035 | 0.1 | Floor : 127mm Slab on Grade | 0 | no
M_Base Cabinet-Double Door & 2 Drawer:1000mm:1000mm:162486 | A103 | 0.6 | 0.86 | 0.035 | 0.1 | Level : Level 1 | 0 | no
M_Base Cabinet-Double Door & 2 Drawer:1000mm:1000mm:162487 | A103 | 0.6 | 0.86 | 0.035 | 0.1 | Level : Level 1 | 0 | no
M_Base Cabinet-Double Door & 2 Drawer:1000mm:1000mm:162488 | A103 | 0.6 | 0.86 | 0.035 | 0.1 | Level : Level 1 | 0 | no
M_Base Cabinet-Double Door & 2 Drawer:1000mm:1000mm:162489 | A103 | 0.6 | 0.86 | 0.035 | 0.1 | Level : Level 1 | 0 | no
M_Base Cabinet-Double Door & 2 Drawer:1000mm:1000mm:162493 | A103 | 0.6 | 0.86 | 0.035 | 0.1 | Level : Level 1 | 0 | no
M_Base Cabinet-Double Door & 2 Drawer:1000mm:1000mm:162495 | A103 | 0.6 | 0.86 | 0.035 | 0.1 | Level : Level 1 | 0 | no
M_Base Cabinet-Double Door & 2 Drawer:1000mm:1000mm:162496 | A103 | 0.6 | 0.86 | 0.035 | 0.1 | Level : Level 1 | 0 | no
M_Base Cabinet-Double Door & 2 Drawer:1000mm:1000mm:162497 | A103 | 0.6 | 0.86 | 0.035 | 0.1 | Level : Level 1 | 0 | no
M_Upper Cabinet-Double Door-Wall:1000mm:1000mm:191768 | A103 | 0.3 | 0.6 | PSet_Revit_Type_Dimensions - Top Of Cabinet: 2 m; PSet_Revit_Constraints - Elevation: 1.4 m
M_Upper Cabinet-Double Door-Wall:1000mm:1000mm:192610 | B103 | 0.3 | 0.6 | PSet_Revit_Type_Dimensions - Top Of Cabinet: 2 m; PSet_Revit_Constraints - Elevation: 1.4 m

# IfcFurnishingElement: 1525 x 2007mm - Queen (2)
Type - ElementType: 1525 x 2007mm - Queen
PSet_Revit_Type_Materials and Finishes - Leg Material: Metal - Chrome; Mattress Material: Textile - White
PSet_Revit_Type_Dimensions - Length: 2.007 m; Width: 1.525 m
PSet_Revit_Type_Identity Data - Manufacturer: Manufacturer; OmniClass Number: 23.40.20.17.14.11; OmniClass Title: Beds
PSet_Revit_Type_Other - AccessibilityPerformance: AccessibilityPerformance; CodePerformance: CodePerformance; Area: Area; Color: Color; Constituents: Constituents; Features: Features; Finish: Finish; Grade: Grade; Material: Material; ModelReference: ModelReference; NominalHeight: NominalHeight; NominalLength: NominalLength; NominalWidth: NominalWidth; ProductionYear: ProductionYear; Reference: Reference; Shape: Shape; Size: Size; SustainabilityPerformance: SustainabilityPerformance; WarrantyDescription: WarrantyDescription; WarrantyDurationLabor: WarrantyDurationLabor; WarrantyDurationParts: WarrantyDurationParts; WarrantyGuarantorLabor: WarrantyGuarantorLabor; WarrantyGuarantorParts: WarrantyGuarantorParts; ExpectedLife: ExpectedLife; ReplacementCost: ReplacementCost; AssetAccountingType: NONFIXED; ModelLabel: ModelLabel
PSet_Revit_Constraints - Level: Level 2; Host: Floor : Residential - Wood Joist with Subflooring; Moves With Nearby Elements: no
PSet_Revit_Other - InstallationDate: InstallationDate; SerialNumber: SerialNumber; WarrantyStartDate: WarrantyStartDate; BarCode: BarCode; AssetIdentifier: AssetIdentifier; TagNumber: TagNumber
PSet_Revit_Phasing - Phase Created: New Construction
Name (M_Bed-Standard:1525 x 2007mm - Queen:1525 x 2007mm - Queen:...) | In
168449 | B203
169008 | A203

# IfcFurnishingElement: 1830mm (4)
Type - ElementType: 1830mm
PSet_Revit_Type_Dimensions - Width: 1.83 m
PSet_Revit_Type_Materials and Finishes - Seat Material: Textile - Linen, Smooth; Frame Material: Wood - Cherry
PSet_Revit_Type_Identity Data - Manufacturer: Manufacturer; OmniClass Number: 23.40.20.14.14.14; OmniClass Title: Settees, Sofas
PSet_Revit_Type_Other - AccessibilityPerformance: AccessibilityPerformance; CodePerformance: CodePerformance; Area: Area; Color: Color; Constituents: Constituents; Features: Features; Finish: Finish; Grade: Grade; Material: Material; ModelReference: ModelReference; NominalHeight: NominalHeight; NominalLength: NominalLength; NominalWidth: NominalWidth; ProductionYear: ProductionYear; Reference: Reference; Shape: Shape; Size: Size; SustainabilityPerformance: SustainabilityPerformance; WarrantyDescription: WarrantyDescription; WarrantyDurationLabor: WarrantyDurationLabor; WarrantyDurationParts: WarrantyDurationParts; WarrantyGuarantorLabor: WarrantyGuarantorLabor; WarrantyGuarantorParts: WarrantyGuarantorParts; ExpectedLife: ExpectedLife; ReplacementCost: ReplacementCost; AssetAccountingType: NONFIXED; ModelLabel: ModelLabel
PSet_Revit_Constraints - Level: Level 1; Host: Floor : 127mm Slab on Grade; Moves With Nearby Elements: no
PSet_Revit_Other - InstallationDate: InstallationDate; SerialNumber: SerialNumber; WarrantyStartDate: WarrantyStartDate; BarCode: BarCode; AssetIdentifier: AssetIdentifier; TagNumber: TagNumber
PSet_Revit_Phasing - Phase Created: New Construction
Name (M_Sofa:1830mm:1830mm:...) | In
167283 | B102
167426 | B102
168377 | A102
168378 | A102

# IfcFurnishingElement: 1981 x 2032mm - King (2)
Type - ElementType: 1981 x 2032mm - King
PSet_Revit_Type_Materials and Finishes - Leg Material: Metal - Chrome; Mattress Material: Textile - White
PSet_Revit_Type_Dimensions - Length: 2.032 m; Width: 1.981 m
PSet_Revit_Type_Identity Data - Manufacturer: Manufacturer; OmniClass Number: 23.40.20.17.14.11; OmniClass Title: Beds
PSet_Revit_Type_Other - AccessibilityPerformance: AccessibilityPerformance; CodePerformance: CodePerformance; Area: Area; Color: Color; Constituents: Constituents; Features: Features; Finish: Finish; Grade: Grade; Material: Material; ModelReference: ModelReference; NominalHeight: NominalHeight; NominalLength: NominalLength; NominalWidth: NominalWidth; ProductionYear: ProductionYear; Reference: Reference; Shape: Shape; Size: Size; SustainabilityPerformance: SustainabilityPerformance; WarrantyDescription: WarrantyDescription; WarrantyDurationLabor: WarrantyDurationLabor; WarrantyDurationParts: WarrantyDurationParts; WarrantyGuarantorLabor: WarrantyGuarantorLabor; WarrantyGuarantorParts: WarrantyGuarantorParts; ExpectedLife: ExpectedLife; ReplacementCost: ReplacementCost; AssetAccountingType: NONFIXED; ModelLabel: ModelLabel
PSet_Revit_Constraints - Level: Level 2; Host: Floor : Residential - Wood Joist with Subflooring; Moves With Nearby Elements: no
PSet_Revit_Other - InstallationDate: InstallationDate; SerialNumber: SerialNumber; WarrantyStartDate: WarrantyStartDate; BarCode: BarCode; AssetIdentifier: AssetIdentifier; TagNumber: TagNumber
PSet_Revit_Phasing - Phase Created: New Construction
Name (M_Bed-Standard:1981 x 2032mm - King:1981 x 2032mm - King:...) | In
168717 | A202
168914 | B202

# IfcFurnishingElement: 450 x 450 mm, M_Vanity Cabinet-Double Door Sink Unit:450 x 450 mm:450 x 450 mm:205548
In: A104
Type - ElementType: 450 x 450 mm
PSet_Revit_Type_Materials and Finishes - Handle Material: Cabinets - Handles; Finish: Finish
PSet_Revit_Type_Dimensions - Depth: 0.45 m; Height: 0.82 m; Plinth Depth: 0.035 m; Plinth Height: 0.1 m; Width: 0.45 m
PSet_Revit_Type_Identity Data - Manufacturer: Manufacturer; OmniClass Number: 23.40.35.17.47.14; OmniClass Title: Bathroom Casework
PSet_Revit_Type_Construction - Construction Type: Construction Type
PSet_Revit_Type_Other - AccessibilityPerformance: AccessibilityPerformance; CodePerformance: CodePerformance; Area: Area; Color: Color; Constituents: Constituents; Features: Features; Finish: Finish; Grade: Grade; Material: Material; ModelReference: ModelReference; NominalHeight: NominalHeight; NominalLength: NominalLength; NominalWidth: NominalWidth; ProductionYear: ProductionYear; Reference: Reference; Shape: Shape; Size: Size; SustainabilityPerformance: SustainabilityPerformance; WarrantyDescription: WarrantyDescription; WarrantyDurationLabor: WarrantyDurationLabor; WarrantyDurationParts: WarrantyDurationParts; WarrantyGuarantorLabor: WarrantyGuarantorLabor; WarrantyGuarantorParts: WarrantyGuarantorParts; ExpectedLife: ExpectedLife; ReplacementCost: ReplacementCost; AssetAccountingType: FIXED; ModelLabel: ModelLabel
PSet_Revit_Constraints - Level: Level 1; Host: Floor : 127mm Slab on Grade; Offset: 0 m; Moves With Nearby Elements: no
PSet_Revit_Other - InstallationDate: InstallationDate; SerialNumber: SerialNumber; WarrantyStartDate: WarrantyStartDate; BarCode: BarCode; AssetIdentifier: AssetIdentifier; TagNumber: TagNumber
PSet_Revit_Phasing - Phase Created: New Construction

# IfcFurnishingElement: 600mm Depth (6)
Type - ElementType: 600mm Depth
PSet_Revit_Type_Dimensions - Counter Thickness: 0.04 m; Depth: 0.625 m; Height: 0.9 m
PSet_Revit_Type_Materials and Finishes - Finish: Finish
PSet_Revit_Type_Identity Data - Manufacturer: Manufacturer; OmniClass Number: 23.40.35.17.47.11; OmniClass Title: Kitchen Casework
PSet_Revit_Type_Construction - Construction Type: Construction Type
PSet_Revit_Type_Other - AccessibilityPerformance: AccessibilityPerformance; CodePerformance: CodePerformance; Area: Area; Color: Color; Constituents: Constituents; Features: Features; Finish: Finish; Grade: Grade; Material: Material; ModelReference: ModelReference; NominalHeight: NominalHeight; NominalLength: NominalLength; NominalWidth: NominalWidth; ProductionYear: ProductionYear; Reference: Reference; Shape: Shape; Size: Size; SustainabilityPerformance: SustainabilityPerformance; WarrantyDescription: WarrantyDescription; WarrantyDurationLabor: WarrantyDurationLabor; WarrantyDurationParts: WarrantyDurationParts; WarrantyGuarantorLabor: WarrantyGuarantorLabor; WarrantyGuarantorParts: WarrantyGuarantorParts; ExpectedLife: ExpectedLife; ReplacementCost: ReplacementCost; AssetAccountingType: FIXED; ModelLabel: ModelLabel
PSet_Revit_Constraints - Level: Level 1; Offset: 0 m; Moves With Nearby Elements: no
PSet_Revit_Other - InstallationDate: InstallationDate; SerialNumber: SerialNumber; WarrantyStartDate: WarrantyStartDate; BarCode: BarCode; AssetIdentifier: AssetIdentifier; TagNumber: TagNumber
PSet_Revit_Phasing - Phase Created: New Construction
Name | In | Length (m) | Host | Backsplash Visibility
M_Counter Top w Sink Hole:600mm Depth:600mm Depth:161165 | B103 | 3 | Floor : 127mm Slab on Grade | PSet_Revit_Dimensions - Sink Location: 1.5 m; Sink Location To Wall: 0.1 m; Sink Opening Depth: 0.378 m; Sink Opening Width: 0.3808 m
M_Counter Top w Sink Hole:600mm Depth:600mm Depth:162490 | A103 | 3 | Level : Level 1 | PSet_Revit_Dimensions - Sink Location: 1.5 m; Sink Location To Wall: 0.1 m; Sink Opening Depth: 0.378 m; Sink Opening Width: 0.3808 m
M_Counter Top:600mm Depth:600mm Depth:161646 | B103 | 1 | Floor : 127mm Slab on Grade | yes
M_Counter Top:600mm Depth:600mm Depth:162231 | B103 | 4.024 | Floor : 127mm Slab on Grade | no
M_Counter Top:600mm Depth:600mm Depth:162491 | A103 | 1 | Level : Level 1 | yes
M_Counter Top:600mm Depth:600mm Depth:162494 | A103 | 4.024 | Level : Level 1 | no

# IfcFurnishingElement: 650 x 450 mm (4)
Type - ElementType: 650 x 450 mm
PSet_Revit_Type_Materials and Finishes - Handle Material: Cabinets - Handles; Finish: Finish
PSet_Revit_Type_Dimensions - Depth: 0.45 m; Height: 0.82 m; Plinth Depth: 0.035 m; Plinth Height: 0.1 m; Width: 0.65 m
PSet_Revit_Type_Identity Data - Manufacturer: Manufacturer; OmniClass Number: 23.40.35.17.47.14; OmniClass Title: Bathroom Casework
PSet_Revit_Type_Construction - Construction Type: Construction Type
PSet_Revit_Type_Other - AccessibilityPerformance: AccessibilityPerformance; CodePerformance: CodePerformance; Area: Area; Color: Color; Constituents: Constituents; Features: Features; Finish: Finish; Grade: Grade; Material: Material; ModelReference: ModelReference; NominalHeight: NominalHeight; NominalLength: NominalLength; NominalWidth: NominalWidth; ProductionYear: ProductionYear; Reference: Reference; Shape: Shape; Size: Size; SustainabilityPerformance: SustainabilityPerformance; WarrantyDescription: WarrantyDescription; WarrantyDurationLabor: WarrantyDurationLabor; WarrantyDurationParts: WarrantyDurationParts; WarrantyGuarantorLabor: WarrantyGuarantorLabor; WarrantyGuarantorParts: WarrantyGuarantorParts; ExpectedLife: ExpectedLife; ReplacementCost: ReplacementCost; AssetAccountingType: FIXED; ModelLabel: ModelLabel
PSet_Revit_Constraints - Level: Level 2; Host: Floor : Finish Floor - Ceramic Tile; Offset: 0 m; Moves With Nearby Elements: no
PSet_Revit_Other - InstallationDate: InstallationDate; SerialNumber: SerialNumber; WarrantyStartDate: WarrantyStartDate; BarCode: BarCode; AssetIdentifier: AssetIdentifier; TagNumber: TagNumber
PSet_Revit_Phasing - Phase Created: New Construction
Name (M_Vanity Cabinet-Double Door Sink Unit:650 x 450 mm:650 x 450 mm:...) | In
204934 | B204
205239 | B204
205264 | A204
205265 | A204

# IfcFurnishingElement: 800 mm (8)
Type - ElementType: 800 mm
PSet_Revit_Type_Materials and Finishes - Handle Material: Cabinets - Handles; Panel Material: Cabinets - Panel; Finish: Finish
PSet_Revit_Type_Dimensions - Depth: 0.52 m; Height: 2 m; Plinth Depth: 0.035 m; Plinth Height: 0.16 m; Width: 0.8 m
PSet_Revit_Type_Identity Data - Manufacturer: Manufacturer; OmniClass Number: 23.40.35.17.47.11; OmniClass Title: Kitchen Casework
PSet_Revit_Type_Construction - Construction Type: Construction Type
PSet_Revit_Type_Other - AccessibilityPerformance: AccessibilityPerformance; CodePerformance: CodePerformance; Area: Area; Color: Color; Constituents: Constituents; Features: Features; Finish: Finish; Grade: Grade; Material: Material; ModelReference: ModelReference; NominalHeight: NominalHeight; NominalLength: NominalLength; NominalWidth: NominalWidth; ProductionYear: ProductionYear; Reference: Reference; Shape: Shape; Size: Size; SustainabilityPerformance: SustainabilityPerformance; WarrantyDescription: WarrantyDescription; WarrantyDurationLabor: WarrantyDurationLabor; WarrantyDurationParts: WarrantyDurationParts; WarrantyGuarantorLabor: WarrantyGuarantorLabor; WarrantyGuarantorParts: WarrantyGuarantorParts; ExpectedLife: ExpectedLife; ReplacementCost: ReplacementCost; AssetAccountingType: FIXED; ModelLabel: ModelLabel
PSet_Revit_Constraints - Level: Level 2; Host: Floor : Residential - Wood Joist with Subflooring; Offset: 0 m; Moves With Nearby Elements: no
PSet_Revit_Other - InstallationDate: InstallationDate; SerialNumber: SerialNumber; WarrantyStartDate: WarrantyStartDate; BarCode: BarCode; AssetIdentifier: AssetIdentifier; TagNumber: TagNumber
PSet_Revit_Phasing - Phase Created: New Construction
Name (M_Tall Cabinet-Single Door(2):800 mm:800 mm:...) | In
157200 | B202
157607 | B202
157950 | A203
157951 | A203
157983 | A202
157984 | A202
158080 | B203
158081 | B203

# IfcOpeningElement: Opening (50)
Name | In
M_Counter Top w Sink Hole:600mm Depth:600mm Depth:161165:1 | B103 | PSet_Revit_Type_Dimensions - Counter Thickness: 0.04 m; Depth: 0.625 m; Height: 0.9 m; PSet_Revit_Type_Materials and Finishes - Finish: Finish; PSet_Revit_Type_Identity Data - Manufacturer: Manufacturer; OmniClass Number: 23.40.35.17.47.11; OmniClass Title: Kitchen Casework; PSet_Revit_Type_Construction - Construction Type: Construction Type; PSet_Revit_Type_Other - AccessibilityPerformance: AccessibilityPerformance; CodePerformance: CodePerformance; Area: Area; Color: Color; Constituents: Constituents; Features: Features; Finish: Finish; Grade: Grade; Material: Material; ModelReference: ModelReference; NominalHeight: NominalHeight; NominalLength: NominalLength; NominalWidth: NominalWidth; ProductionYear: ProductionYear; Reference: Reference; Shape: Shape; Size: Size; SustainabilityPerformance: SustainabilityPerformance; WarrantyDescription: WarrantyDescription; WarrantyDurationLabor: WarrantyDurationLabor; WarrantyDurationParts: WarrantyDurationParts; WarrantyGuarantorLabor: WarrantyGuarantorLabor; WarrantyGuarantorParts: WarrantyGuarantorParts; ExpectedLife: ExpectedLife; ReplacementCost: ReplacementCost; AssetAccountingType: FIXED; ModelLabel: ModelLabel; PSet_Revit_Dimensions - Length: 3 m; Sink Location: 1.5 m; Sink Location To Wall: 0.1 m; Sink Opening Depth: 0.378 m; Sink Opening Width: 0.3808 m; PSet_Revit_Constraints - Level: Level 1; Host: Floor : 127mm Slab on Grade; Offset: 0 m; Moves With Nearby Elements: no; PSet_Revit_Other - InstallationDate: InstallationDate; SerialNumber: SerialNumber; WarrantyStartDate: WarrantyStartDate; BarCode: BarCode; AssetIdentifier: AssetIdentifier; TagNumber: TagNumber; PSet_Revit_Phasing - Phase Created: New Construction
M_Counter Top w Sink Hole:600mm Depth:600mm Depth:162490:1 | A103 | PSet_Revit_Type_Dimensions - Counter Thickness: 0.04 m; Depth: 0.625 m; Height: 0.9 m; PSet_Revit_Type_Materials and Finishes - Finish: Finish; PSet_Revit_Type_Identity Data - Manufacturer: Manufacturer; OmniClass Number: 23.40.35.17.47.11; OmniClass Title: Kitchen Casework; PSet_Revit_Type_Construction - Construction Type: Construction Type; PSet_Revit_Type_Other - AccessibilityPerformance: AccessibilityPerformance; CodePerformance: CodePerformance; Area: Area; Color: Color; Constituents: Constituents; Features: Features; Finish: Finish; Grade: Grade; Material: Material; ModelReference: ModelReference; NominalHeight: NominalHeight; NominalLength: NominalLength; NominalWidth: NominalWidth; ProductionYear: ProductionYear; Reference: Reference; Shape: Shape; Size: Size; SustainabilityPerformance: SustainabilityPerformance; WarrantyDescription: WarrantyDescription; WarrantyDurationLabor: WarrantyDurationLabor; WarrantyDurationParts: WarrantyDurationParts; WarrantyGuarantorLabor: WarrantyGuarantorLabor; WarrantyGuarantorParts: WarrantyGuarantorParts; ExpectedLife: ExpectedLife; ReplacementCost: ReplacementCost; AssetAccountingType: FIXED; ModelLabel: ModelLabel; PSet_Revit_Dimensions - Length: 3 m; Sink Location: 1.5 m; Sink Location To Wall: 0.1 m; Sink Opening Depth: 0.378 m; Sink Opening Width: 0.3808 m; PSet_Revit_Constraints - Level: Level 1; Host: Level : Level 1; Offset: 0 m; Moves With Nearby Elements: no; PSet_Revit_Other - InstallationDate: InstallationDate; SerialNumber: SerialNumber; WarrantyStartDate: WarrantyStartDate; BarCode: BarCode; AssetIdentifier: AssetIdentifier; TagNumber: TagNumber; PSet_Revit_Phasing - Phase Created: New Construction
M_Tall Cabinet-Single Door(2):800 mm:800 mm:157200:1 | B202 | PSet_Revit_Type_Dimensions - Depth: 0.52 m; Height: 2 m; Plinth Depth: 0.035 m; Plinth Height: 0.16 m; Width: 0.8 m; PSet_Revit_Type_Materials and Finishes - Finish: Finish; Handle Material: Cabinets - Handles; Panel Material: Cabinets - Panel; PSet_Revit_Type_Identity Data - Manufacturer: Manufacturer; OmniClass Number: 23.40.35.17.47.11; OmniClass Title: Kitchen Casework; PSet_Revit_Type_Construction - Construction Type: Construction Type; PSet_Revit_Type_Other - AccessibilityPerformance: AccessibilityPerformance; CodePerformance: CodePerformance; Area: Area; Color: Color; Constituents: Constituents; Features: Features; Finish: Finish; Grade: Grade; Material: Material; ModelReference: ModelReference; NominalHeight: NominalHeight; NominalLength: NominalLength; NominalWidth: NominalWidth; ProductionYear: ProductionYear; Reference: Reference; Shape: Shape; Size: Size; SustainabilityPerformance: SustainabilityPerformance; WarrantyDescription: WarrantyDescription; WarrantyDurationLabor: WarrantyDurationLabor; WarrantyDurationParts: WarrantyDurationParts; WarrantyGuarantorLabor: WarrantyGuarantorLabor; WarrantyGuarantorParts: WarrantyGuarantorParts; ExpectedLife: ExpectedLife; ReplacementCost: ReplacementCost; AssetAccountingType: FIXED; ModelLabel: ModelLabel; PSet_Revit_Constraints - Level: Level 2; Host: Floor : Residential - Wood Joist with Subflooring; Offset: 0 m; Moves With Nearby Elements: no; PSet_Revit_Other - InstallationDate: InstallationDate; SerialNumber: SerialNumber; WarrantyStartDate: WarrantyStartDate; BarCode: BarCode; AssetIdentifier: AssetIdentifier; TagNumber: TagNumber; PSet_Revit_Phasing - Phase Created: New Construction
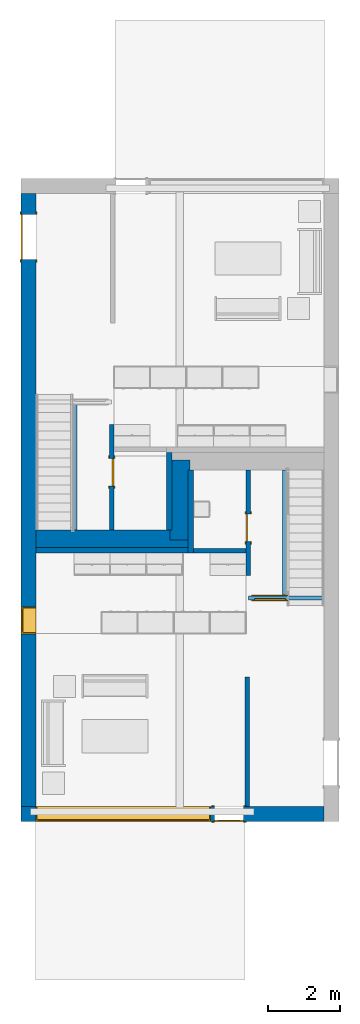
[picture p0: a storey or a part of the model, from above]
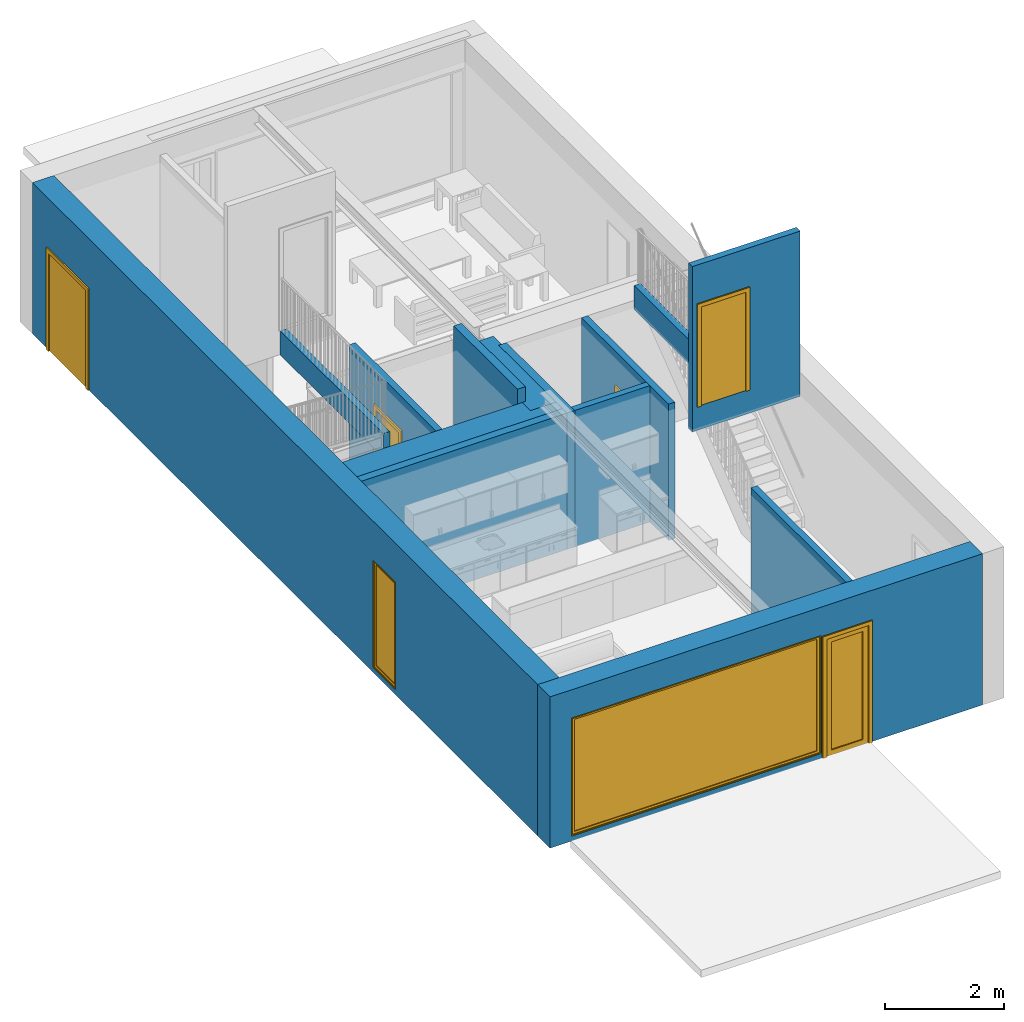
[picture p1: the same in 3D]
Properties of the parts of a building model (IFC4), part 2 of 3

# IfcOpeningElement: Opening (50)
Name | In
M_Tall Cabinet-Single Door(2):800 mm:800 mm:157607:1 | B202 | PSet_Revit_Type_Dimensions - Depth: 0.52 m; Height: 2 m; Plinth Depth: 0.035 m; Plinth Height: 0.16 m; Width: 0.8 m; PSet_Revit_Type_Materials and Finishes - Finish: Finish; Handle Material: Cabinets - Handles; Panel Material: Cabinets - Panel; PSet_Revit_Type_Identity Data - Manufacturer: Manufacturer; OmniClass Number: 23.40.35.17.47.11; OmniClass Title: Kitchen Casework; PSet_Revit_Type_Construction - Construction Type: Construction Type; PSet_Revit_Type_Other - AccessibilityPerformance: AccessibilityPerformance; CodePerformance: CodePerformance; Area: Area; Color: Color; Constituents: Constituents; Features: Features; Finish: Finish; Grade: Grade; Material: Material; ModelReference: ModelReference; NominalHeight: NominalHeight; NominalLength: NominalLength; NominalWidth: NominalWidth; ProductionYear: ProductionYear; Reference: Reference; Shape: Shape; Size: Size; SustainabilityPerformance: SustainabilityPerformance; WarrantyDescription: WarrantyDescription; WarrantyDurationLabor: WarrantyDurationLabor; WarrantyDurationParts: WarrantyDurationParts; WarrantyGuarantorLabor: WarrantyGuarantorLabor; WarrantyGuarantorParts: WarrantyGuarantorParts; ExpectedLife: ExpectedLife; ReplacementCost: ReplacementCost; AssetAccountingType: FIXED; ModelLabel: ModelLabel; PSet_Revit_Constraints - Level: Level 2; Host: Floor : Residential - Wood Joist with Subflooring; Offset: 0 m; Moves With Nearby Elements: no; PSet_Revit_Other - InstallationDate: InstallationDate; SerialNumber: SerialNumber; WarrantyStartDate: WarrantyStartDate; BarCode: BarCode; AssetIdentifier: AssetIdentifier; TagNumber: TagNumber; PSet_Revit_Phasing - Phase Created: New Construction
M_Tall Cabinet-Single Door(2):800 mm:800 mm:157950:1 | A203 | PSet_Revit_Type_Dimensions - Depth: 0.52 m; Height: 2 m; Plinth Depth: 0.035 m; Plinth Height: 0.16 m; Width: 0.8 m; PSet_Revit_Type_Materials and Finishes - Finish: Finish; Handle Material: Cabinets - Handles; Panel Material: Cabinets - Panel; PSet_Revit_Type_Identity Data - Manufacturer: Manufacturer; OmniClass Number: 23.40.35.17.47.11; OmniClass Title: Kitchen Casework; PSet_Revit_Type_Construction - Construction Type: Construction Type; PSet_Revit_Type_Other - AccessibilityPerformance: AccessibilityPerformance; CodePerformance: CodePerformance; Area: Area; Color: Color; Constituents: Constituents; Features: Features; Finish: Finish; Grade: Grade; Material: Material; ModelReference: ModelReference; NominalHeight: NominalHeight; NominalLength: NominalLength; NominalWidth: NominalWidth; ProductionYear: ProductionYear; Reference: Reference; Shape: Shape; Size: Size; SustainabilityPerformance: SustainabilityPerformance; WarrantyDescription: WarrantyDescription; WarrantyDurationLabor: WarrantyDurationLabor; WarrantyDurationParts: WarrantyDurationParts; WarrantyGuarantorLabor: WarrantyGuarantorLabor; WarrantyGuarantorParts: WarrantyGuarantorParts; ExpectedLife: ExpectedLife; ReplacementCost: ReplacementCost; AssetAccountingType: FIXED; ModelLabel: ModelLabel; PSet_Revit_Constraints - Level: Level 2; Host: Floor : Residential - Wood Joist with Subflooring; Offset: 0 m; Moves With Nearby Elements: no; PSet_Revit_Other - InstallationDate: InstallationDate; SerialNumber: SerialNumber; WarrantyStartDate: WarrantyStartDate; BarCode: BarCode; AssetIdentifier: AssetIdentifier; TagNumber: TagNumber; PSet_Revit_Phasing - Phase Created: New Construction
M_Tall Cabinet-Single Door(2):800 mm:800 mm:157951:1 | A203 | PSet_Revit_Type_Dimensions - Depth: 0.52 m; Height: 2 m; Plinth Depth: 0.035 m; Plinth Height: 0.16 m; Width: 0.8 m; PSet_Revit_Type_Materials and Finishes - Finish: Finish; Handle Material: Cabinets - Handles; Panel Material: Cabinets - Panel; PSet_Revit_Type_Identity Data - Manufacturer: Manufacturer; OmniClass Number: 23.40.35.17.47.11; OmniClass Title: Kitchen Casework; PSet_Revit_Type_Construction - Construction Type: Construction Type; PSet_Revit_Type_Other - AccessibilityPerformance: AccessibilityPerformance; CodePerformance: CodePerformance; Area: Area; Color: Color; Constituents: Constituents; Features: Features; Finish: Finish; Grade: Grade; Material: Material; ModelReference: ModelReference; NominalHeight: NominalHeight; NominalLength: NominalLength; NominalWidth: NominalWidth; ProductionYear: ProductionYear; Reference: Reference; Shape: Shape; Size: Size; SustainabilityPerformance: SustainabilityPerformance; WarrantyDescription: WarrantyDescription; WarrantyDurationLabor: WarrantyDurationLabor; WarrantyDurationParts: WarrantyDurationParts; WarrantyGuarantorLabor: WarrantyGuarantorLabor; WarrantyGuarantorParts: WarrantyGuarantorParts; ExpectedLife: ExpectedLife; ReplacementCost: ReplacementCost; AssetAccountingType: FIXED; ModelLabel: ModelLabel; PSet_Revit_Constraints - Level: Level 2; Host: Floor : Residential - Wood Joist with Subflooring; Offset: 0 m; Moves With Nearby Elements: no; PSet_Revit_Other - InstallationDate: InstallationDate; SerialNumber: SerialNumber; WarrantyStartDate: WarrantyStartDate; BarCode: BarCode; AssetIdentifier: AssetIdentifier; TagNumber: TagNumber; PSet_Revit_Phasing - Phase Created: New Construction
M_Tall Cabinet-Single Door(2):800 mm:800 mm:157983:1 | A202 | PSet_Revit_Type_Dimensions - Depth: 0.52 m; Height: 2 m; Plinth Depth: 0.035 m; Plinth Height: 0.16 m; Width: 0.8 m; PSet_Revit_Type_Materials and Finishes - Finish: Finish; Handle Material: Cabinets - Handles; Panel Material: Cabinets - Panel; PSet_Revit_Type_Identity Data - Manufacturer: Manufacturer; OmniClass Number: 23.40.35.17.47.11; OmniClass Title: Kitchen Casework; PSet_Revit_Type_Construction - Construction Type: Construction Type; PSet_Revit_Type_Other - AccessibilityPerformance: AccessibilityPerformance; CodePerformance: CodePerformance; Area: Area; Color: Color; Constituents: Constituents; Features: Features; Finish: Finish; Grade: Grade; Material: Material; ModelReference: ModelReference; NominalHeight: NominalHeight; NominalLength: NominalLength; NominalWidth: NominalWidth; ProductionYear: ProductionYear; Reference: Reference; Shape: Shape; Size: Size; SustainabilityPerformance: SustainabilityPerformance; WarrantyDescription: WarrantyDescription; WarrantyDurationLabor: WarrantyDurationLabor; WarrantyDurationParts: WarrantyDurationParts; WarrantyGuarantorLabor: WarrantyGuarantorLabor; WarrantyGuarantorParts: WarrantyGuarantorParts; ExpectedLife: ExpectedLife; ReplacementCost: ReplacementCost; AssetAccountingType: FIXED; ModelLabel: ModelLabel; PSet_Revit_Constraints - Level: Level 2; Host: Floor : Residential - Wood Joist with Subflooring; Offset: 0 m; Moves With Nearby Elements: no; PSet_Revit_Other - InstallationDate: InstallationDate; SerialNumber: SerialNumber; WarrantyStartDate: WarrantyStartDate; BarCode: BarCode; AssetIdentifier: AssetIdentifier; TagNumber: TagNumber; PSet_Revit_Phasing - Phase Created: New Construction
M_Tall Cabinet-Single Door(2):800 mm:800 mm:157984:1 | A202 | PSet_Revit_Type_Dimensions - Depth: 0.52 m; Height: 2 m; Plinth Depth: 0.035 m; Plinth Height: 0.16 m; Width: 0.8 m; PSet_Revit_Type_Materials and Finishes - Finish: Finish; Handle Material: Cabinets - Handles; Panel Material: Cabinets - Panel; PSet_Revit_Type_Identity Data - Manufacturer: Manufacturer; OmniClass Number: 23.40.35.17.47.11; OmniClass Title: Kitchen Casework; PSet_Revit_Type_Construction - Construction Type: Construction Type; PSet_Revit_Type_Other - AccessibilityPerformance: AccessibilityPerformance; CodePerformance: CodePerformance; Area: Area; Color: Color; Constituents: Constituents; Features: Features; Finish: Finish; Grade: Grade; Material: Material; ModelReference: ModelReference; NominalHeight: NominalHeight; NominalLength: NominalLength; NominalWidth: NominalWidth; ProductionYear: ProductionYear; Reference: Reference; Shape: Shape; Size: Size; SustainabilityPerformance: SustainabilityPerformance; WarrantyDescription: WarrantyDescription; WarrantyDurationLabor: WarrantyDurationLabor; WarrantyDurationParts: WarrantyDurationParts; WarrantyGuarantorLabor: WarrantyGuarantorLabor; WarrantyGuarantorParts: WarrantyGuarantorParts; ExpectedLife: ExpectedLife; ReplacementCost: ReplacementCost; AssetAccountingType: FIXED; ModelLabel: ModelLabel; PSet_Revit_Constraints - Level: Level 2; Host: Floor : Residential - Wood Joist with Subflooring; Offset: 0 m; Moves With Nearby Elements: no; PSet_Revit_Other - InstallationDate: InstallationDate; SerialNumber: SerialNumber; WarrantyStartDate: WarrantyStartDate; BarCode: BarCode; AssetIdentifier: AssetIdentifier; TagNumber: TagNumber; PSet_Revit_Phasing - Phase Created: New Construction
M_Tall Cabinet-Single Door(2):800 mm:800 mm:158080:1 | B203 | PSet_Revit_Type_Dimensions - Depth: 0.52 m; Height: 2 m; Plinth Depth: 0.035 m; Plinth Height: 0.16 m; Width: 0.8 m; PSet_Revit_Type_Materials and Finishes - Finish: Finish; Handle Material: Cabinets - Handles; Panel Material: Cabinets - Panel; PSet_Revit_Type_Identity Data - Manufacturer: Manufacturer; OmniClass Number: 23.40.35.17.47.11; OmniClass Title: Kitchen Casework; PSet_Revit_Type_Construction - Construction Type: Construction Type; PSet_Revit_Type_Other - AccessibilityPerformance: AccessibilityPerformance; CodePerformance: CodePerformance; Area: Area; Color: Color; Constituents: Constituents; Features: Features; Finish: Finish; Grade: Grade; Material: Material; ModelReference: ModelReference; NominalHeight: NominalHeight; NominalLength: NominalLength; NominalWidth: NominalWidth; ProductionYear: ProductionYear; Reference: Reference; Shape: Shape; Size: Size; SustainabilityPerformance: SustainabilityPerformance; WarrantyDescription: WarrantyDescription; WarrantyDurationLabor: WarrantyDurationLabor; WarrantyDurationParts: WarrantyDurationParts; WarrantyGuarantorLabor: WarrantyGuarantorLabor; WarrantyGuarantorParts: WarrantyGuarantorParts; ExpectedLife: ExpectedLife; ReplacementCost: ReplacementCost; AssetAccountingType: FIXED; ModelLabel: ModelLabel; PSet_Revit_Constraints - Level: Level 2; Host: Floor : Residential - Wood Joist with Subflooring; Offset: 0 m; Moves With Nearby Elements: no; PSet_Revit_Other - InstallationDate: InstallationDate; SerialNumber: SerialNumber; WarrantyStartDate: WarrantyStartDate; BarCode: BarCode; AssetIdentifier: AssetIdentifier; TagNumber: TagNumber; PSet_Revit_Phasing - Phase Created: New Construction
M_Tall Cabinet-Single Door(2):800 mm:800 mm:158081:1 | B203 | PSet_Revit_Type_Dimensions - Depth: 0.52 m; Height: 2 m; Plinth Depth: 0.035 m; Plinth Height: 0.16 m; Width: 0.8 m; PSet_Revit_Type_Materials and Finishes - Finish: Finish; Handle Material: Cabinets - Handles; Panel Material: Cabinets - Panel; PSet_Revit_Type_Identity Data - Manufacturer: Manufacturer; OmniClass Number: 23.40.35.17.47.11; OmniClass Title: Kitchen Casework; PSet_Revit_Type_Construction - Construction Type: Construction Type; PSet_Revit_Type_Other - AccessibilityPerformance: AccessibilityPerformance; CodePerformance: CodePerformance; Area: Area; Color: Color; Constituents: Constituents; Features: Features; Finish: Finish; Grade: Grade; Material: Material; ModelReference: ModelReference; NominalHeight: NominalHeight; NominalLength: NominalLength; NominalWidth: NominalWidth; ProductionYear: ProductionYear; Reference: Reference; Shape: Shape; Size: Size; SustainabilityPerformance: SustainabilityPerformance; WarrantyDescription: WarrantyDescription; WarrantyDurationLabor: WarrantyDurationLabor; WarrantyDurationParts: WarrantyDurationParts; WarrantyGuarantorLabor: WarrantyGuarantorLabor; WarrantyGuarantorParts: WarrantyGuarantorParts; ExpectedLife: ExpectedLife; ReplacementCost: ReplacementCost; AssetAccountingType: FIXED; ModelLabel: ModelLabel; PSet_Revit_Constraints - Level: Level 2; Host: Floor : Residential - Wood Joist with Subflooring; Offset: 0 m; Moves With Nearby Elements: no; PSet_Revit_Other - InstallationDate: InstallationDate; SerialNumber: SerialNumber; WarrantyStartDate: WarrantyStartDate; BarCode: BarCode; AssetIdentifier: AssetIdentifier; TagNumber: TagNumber; PSet_Revit_Phasing - Phase Created: New Construction
2 x  | Roof | PSet_Revit_Type_Identity Data - Manufacturer: Manufacturer; PSet_Revit_Type_Other - AccessibilityPerformance: AccessibilityPerformance; CodePerformance: CodePerformance; Color: Color; Constituents: Constituents; Features: Features; Finish: Finish; Grade: Grade; Material: Material; ModelReference: ModelReference; NominalHeight: NominalHeight; NominalLength: NominalLength; NominalWidth: NominalWidth; ProductionYear: ProductionYear; Reference: Reference; Shape: Shape; Size: Size; SustainabilityPerformance: SustainabilityPerformance; WarrantyDescription: WarrantyDescription; WarrantyDurationLabor: WarrantyDurationLabor; WarrantyDurationParts: WarrantyDurationParts; WarrantyGuarantorLabor: WarrantyGuarantorLabor; WarrantyGuarantorParts: WarrantyGuarantorParts; ExpectedLife: ExpectedLife; ReplacementCost: ReplacementCost; AssetAccountingType: FIXED; ModelLabel: ModelLabel; Classification Description: Structural Roof Decks; Classification Code: 23-25 30 27 14; PSet_Revit_Other - InstallationDate: InstallationDate; SerialNumber: SerialNumber; WarrantyStartDate: WarrantyStartDate; BarCode: BarCode; AssetIdentifier: AssetIdentifier; TagNumber: TagNumber; PSet_Revit_Phasing - Phase Created: New Construction; PSet_Revit_Type_Construction - Default Thickness: 0.457 m; PSet_Revit_Type_Graphics - Coarse Scale Fill Color: 0; PSet_Revit_Constraints - Base Level: Roof; Room Bounding: no; Related to Mass: no; Base Offset From Level: 0 m; Cutoff Offset: 0 m; PSet_Revit_Construction - Rafter Cut: 33615; Fascia Depth: 0 m; Maximum Ridge Height: 6.457 m; PSet_Revit_Dimensions - Thickness: 0.457 m; Volume: 60.7472 m3; Area: 132.926 m2; Pset_RoofCommon - Reference: Basic Roof:Live Roof over Wood Joist Flat Roof; IsExternal: no; TotalArea: 132.926 m2; ProjectedArea: 135.151 m2
Basic Roof:Live Roof over Wood Joist Flat Roof:184483:2 | Roof | PSet_Revit_Type_Identity Data - Manufacturer: Manufacturer; PSet_Revit_Type_Other - AccessibilityPerformance: AccessibilityPerformance; CodePerformance: CodePerformance; Color: Color; Constituents: Constituents; Features: Features; Finish: Finish; Grade: Grade; Material: Material; ModelReference: ModelReference; NominalHeight: NominalHeight; NominalLength: NominalLength; NominalWidth: NominalWidth; ProductionYear: ProductionYear; Reference: Reference; Shape: Shape; Size: Size; SustainabilityPerformance: SustainabilityPerformance; WarrantyDescription: WarrantyDescription; WarrantyDurationLabor: WarrantyDurationLabor; WarrantyDurationParts: WarrantyDurationParts; WarrantyGuarantorLabor: WarrantyGuarantorLabor; WarrantyGuarantorParts: WarrantyGuarantorParts; ExpectedLife: ExpectedLife; ReplacementCost: ReplacementCost; AssetAccountingType: FIXED; ModelLabel: ModelLabel; Classification Description: Structural Roof Decks; Classification Code: 23-25 30 27 14; PSet_Revit_Other - InstallationDate: InstallationDate; SerialNumber: SerialNumber; WarrantyStartDate: WarrantyStartDate; BarCode: BarCode; AssetIdentifier: AssetIdentifier; TagNumber: TagNumber; PSet_Revit_Phasing - Phase Created: New Construction; PSet_Revit_Type_Construction - Default Thickness: 0.457 m; PSet_Revit_Type_Graphics - Coarse Scale Fill Color: 0; PSet_Revit_Constraints - Base Level: Roof; Room Bounding: no; Related to Mass: no; Base Offset From Level: 0 m; Cutoff Offset: 0 m; PSet_Revit_Construction - Rafter Cut: 33615; Fascia Depth: 0 m; Maximum Ridge Height: 6.457 m; PSet_Revit_Dimensions - Thickness: 0.457 m; Volume: 60.7472 m3; Area: 132.926 m2; Pset_RoofCommon - Reference: Basic Roof:Live Roof over Wood Joist Flat Roof; IsExternal: no; TotalArea: 132.926 m2; ProjectedArea: 135.151 m2
Basic Roof:Live Roof over Wood Joist Flat Roof:184483:3 | Roof | PSet_Revit_Type_Identity Data - Manufacturer: Manufacturer; PSet_Revit_Type_Other - AccessibilityPerformance: AccessibilityPerformance; CodePerformance: CodePerformance; Color: Color; Constituents: Constituents; Features: Features; Finish: Finish; Grade: Grade; Material: Material; ModelReference: ModelReference; NominalHeight: NominalHeight; NominalLength: NominalLength; NominalWidth: NominalWidth; ProductionYear: ProductionYear; Reference: Reference; Shape: Shape; Size: Size; SustainabilityPerformance: SustainabilityPerformance; WarrantyDescription: WarrantyDescription; WarrantyDurationLabor: WarrantyDurationLabor; WarrantyDurationParts: WarrantyDurationParts; WarrantyGuarantorLabor: WarrantyGuarantorLabor; WarrantyGuarantorParts: WarrantyGuarantorParts; ExpectedLife: ExpectedLife; ReplacementCost: ReplacementCost; AssetAccountingType: FIXED; ModelLabel: ModelLabel; Classification Description: Structural Roof Decks; Classification Code: 23-25 30 27 14; PSet_Revit_Other - InstallationDate: InstallationDate; SerialNumber: SerialNumber; WarrantyStartDate: WarrantyStartDate; BarCode: BarCode; AssetIdentifier: AssetIdentifier; TagNumber: TagNumber; PSet_Revit_Phasing - Phase Created: New Construction; PSet_Revit_Type_Construction - Default Thickness: 0.457 m; PSet_Revit_Type_Graphics - Coarse Scale Fill Color: 0; PSet_Revit_Constraints - Base Level: Roof; Room Bounding: no; Related to Mass: no; Base Offset From Level: 0 m; Cutoff Offset: 0 m; PSet_Revit_Construction - Rafter Cut: 33615; Fascia Depth: 0 m; Maximum Ridge Height: 6.457 m; PSet_Revit_Dimensions - Thickness: 0.457 m; Volume: 60.7472 m3; Area: 132.926 m2; Pset_RoofCommon - Reference: Basic Roof:Live Roof over Wood Joist Flat Roof; IsExternal: no; TotalArea: 132.926 m2; ProjectedArea: 135.151 m2
M_Single-Flush:0762 x 2032mm:0762 x 2032mm:204034:1 | Level 2
M_Single-Flush:0762 x 2032mm:0762 x 2032mm:203720:1 | Level 2
M_Fixed:750mm x 2200mm:750mm x 2200mm:182101:1 | Level 2
M_Fixed:750mm x 2200mm:750mm x 2200mm:181930:1 | Level 2
M_Fixed:819mm x 759mm:819mm x 759mm:181583:1 | Level 2
M_Casement:819mm x 759mm:819mm x 759mm:181548:1 | Level 2
M_Fixed:2800mm x 2410mm:2800mm x 2410mm:181096:1 | Level 2
M_Fixed:819mm x 759mm:819mm x 759mm:181285:1 | Level 2
M_Casement:819mm x 759mm:819mm x 759mm:180994:1 | Level 2
M_Fixed:819mm x 759mm:819mm x 759mm:180864:1 | Level 2
M_Fixed:819mm x 759mm:819mm x 759mm:180663:1 | Level 2
M_Single-Glass 1:0813 x 2420mm:0813 x 2420mm:171975:1 | Level 1
M_Fixed:2800mm x 2410mm:2800mm x 2410mm:180318:1 | Level 2
M_Single-Glass 1:0813 x 2420mm:0813 x 2420mm:171853:1 | Level 1
M_Single-Flush:0864 x 2032mm:0864 x 2032mm:160208:1 | Level 2
M_Single-Flush:0864 x 2032mm:0864 x 2032mm:160065:1 | Level 2
M_Single-Flush:0864 x 2032mm:0864 x 2032mm:159834:1 | Level 2
M_Single-Flush:0864 x 2032mm:0864 x 2032mm:159734:1 | Level 2
M_Single-Flush:0864 x 2032mm:0864 x 2032mm:150478:1 | Level 1
M_Single-Flush:0864 x 2032mm:0864 x 2032mm:150378:1 | Level 1
M_Single-Flush:0762 x 2032mm:0762 x 2032mm:150257:1 | Level 1
M_Single-Flush:0762 x 2032mm:0762 x 2032mm:150173:1 | Level 1
M_Fixed:819mm x 759mm:819mm x 759mm:149924:1 | Level 2
M_Casement:819mm x 759mm:819mm x 759mm:149736:1 | Level 2
M_Fixed:2800mm x 2410mm:2800mm x 2410mm:149278:1 | Level 2
M_Fixed:819mm x 759mm:819mm x 759mm:149537:1 | Level 2
M_Fixed:819mm x 759mm:819mm x 759mm:148722:1 | Level 2
M_Casement:819mm x 759mm:819mm x 759mm:148607:1 | Level 2
M_Fixed:819mm x 759mm:819mm x 759mm:147994:1 | Level 2
M_Fixed:2800mm x 2410mm:2800mm x 2410mm:147686:1 | Level 2
M_Fixed:750mm x 2200mm:750mm x 2200mm:147051:1 | Level 1
M_Fixed:750mm x 2200mm:750mm x 2200mm:146885:1 | Level 1
M_Single-Flush:1250mm x 2010mm:1250mm x 2010mm:146596:1 | Level 1
M_Single-Flush:1250mm x 2010mm:1250mm x 2010mm:146678:1 | Level 1
M_Fixed:4835mm x 2420mm:4835mm x 2420mm:146016:1 | Level 1
M_Fixed:4835mm x 2420mm:4835mm x 2420mm:145788:1 | Level 1

# IfcRailing: Railing:1100mm Guard Rail (2)
In: Level 1
PSet_Revit_Type_Construction - Railing Height: 1.1 m; Baluster Offset: -0.025 m; Use Landing Height Adjustment: 0; Landing Height Adjustment: 0 m; Angled Joins: 0; Tangent Joins: 2; Rail Connections: 0
PSet_Revit_Type_Identity Data - Manufacturer: Manufacturer
PSet_Revit_Type_Other - AccessibilityPerformance: AccessibilityPerformance; CodePerformance: CodePerformance; Color: Color; Constituents: Constituents; Features: Features; Finish: Finish; Grade: Grade; Material: Material; ModelReference: ModelReference; NominalHeight: NominalHeight; NominalLength: NominalLength; NominalWidth: NominalWidth; ProductionYear: ProductionYear; Reference: Reference; Shape: Shape; Size: Size; SustainabilityPerformance: SustainabilityPerformance; WarrantyDescription: WarrantyDescription; WarrantyDurationLabor: WarrantyDurationLabor; WarrantyDurationParts: WarrantyDurationParts; WarrantyGuarantorLabor: WarrantyGuarantorLabor; WarrantyGuarantorParts: WarrantyGuarantorParts; ExpectedLife: ExpectedLife; ReplacementCost: ReplacementCost; AssetAccountingType: FIXED; Classification Description: Guardrails; Classification Code: 23-30 80 11; ModelLabel: ModelLabel
PSet_Revit_Dimensions - Length: 8.33434 m
PSet_Revit_Constraints - Base Offset: 0 m
PSet_Revit_Other - InstallationDate: InstallationDate; SerialNumber: SerialNumber; WarrantyStartDate: WarrantyStartDate; BarCode: BarCode; AssetIdentifier: AssetIdentifier; TagNumber: TagNumber
PSet_Revit_Phasing - Phase Created: New Construction
Pset_RailingCommon - Reference: Railing:1100mm Guard Rail; IsExternal: no; Height: 1.1
Name (Railing:1100mm Guard Rail:...)
151166
198972

# IfcRailing: Railing:900mm Handrail Only (2)
In: Level 1
PSet_Revit_Type_Construction - Railing Height: 0.9 m; Baluster Offset: -0.025 m; Use Landing Height Adjustment: 0; Landing Height Adjustment: 0 m; Angled Joins: 0; Tangent Joins: 2; Rail Connections: 0
PSet_Revit_Type_Identity Data - Manufacturer: Manufacturer
PSet_Revit_Type_Other - AccessibilityPerformance: AccessibilityPerformance; CodePerformance: CodePerformance; Color: Color; Constituents: Constituents; Features: Features; Finish: Finish; Grade: Grade; Material: Material; ModelReference: ModelReference; NominalHeight: NominalHeight; NominalLength: NominalLength; NominalWidth: NominalWidth; ProductionYear: ProductionYear; Reference: Reference; Shape: Shape; Size: Size; SustainabilityPerformance: SustainabilityPerformance; WarrantyDescription: WarrantyDescription; WarrantyDurationLabor: WarrantyDurationLabor; WarrantyDurationParts: WarrantyDurationParts; WarrantyGuarantorLabor: WarrantyGuarantorLabor; WarrantyGuarantorParts: WarrantyGuarantorParts; ExpectedLife: ExpectedLife; ReplacementCost: ReplacementCost; AssetAccountingType: FIXED; Classification Description: Handrails; Classification Code: 23-30 80 14; ModelLabel: ModelLabel
PSet_Revit_Dimensions - Length: 4.74434 m
PSet_Revit_Constraints - Base Offset: 0 m
PSet_Revit_Other - InstallationDate: InstallationDate; SerialNumber: SerialNumber; WarrantyStartDate: WarrantyStartDate; BarCode: BarCode; AssetIdentifier: AssetIdentifier; TagNumber: TagNumber
PSet_Revit_Phasing - Phase Created: New Construction
Pset_RailingCommon - Reference: Railing:900mm Handrail Only; IsExternal: no; Height: 0.9
Name (Railing:900mm Handrail Only:...)
151162
198880

# IfcRoof: Basic Roof:Live Roof over Wood Joist Flat Roof, Basic Roof:Live Roof over Wood Joist Flat Roof:184483
In: Roof
Material: Site - Grass 0.064 m, Roofing - Barrier 0.006 m, Roofing - EPDM Membrane 0.006 m, Insulation / Thermal Barriers - Rigid insulation 0.076 m, Wood - Sheathing - plywood 0.019 m, Wood - Dimensional Lumber 0.286 m
PSet_Revit_Type_Construction - Default Thickness: 0.457 m
PSet_Revit_Type_Graphics - Coarse Scale Fill Color: 0
PSet_Revit_Type_Identity Data - Manufacturer: Manufacturer
PSet_Revit_Type_Other - AccessibilityPerformance: AccessibilityPerformance; CodePerformance: CodePerformance; Color: Color; Constituents: Constituents; Features: Features; Finish: Finish; Grade: Grade; Material: Material; ModelReference: ModelReference; NominalHeight: NominalHeight; NominalLength: NominalLength; NominalWidth: NominalWidth; ProductionYear: ProductionYear; Reference: Reference; Shape: Shape; Size: Size; SustainabilityPerformance: SustainabilityPerformance; WarrantyDescription: WarrantyDescription; WarrantyDurationLabor: WarrantyDurationLabor; WarrantyDurationParts: WarrantyDurationParts; WarrantyGuarantorLabor: WarrantyGuarantorLabor; WarrantyGuarantorParts: WarrantyGuarantorParts; ExpectedLife: ExpectedLife; ReplacementCost: ReplacementCost; AssetAccountingType: FIXED; Classification Description: Structural Roof Decks; Classification Code: 23-25 30 27 14; ModelLabel: ModelLabel
PSet_Revit_Constraints - Base Level: Roof; Room Bounding: no; Related to Mass: no; Base Offset From Level: 0 m; Cutoff Offset: 0 m
PSet_Revit_Construction - Rafter Cut: 33615; Fascia Depth: 0 m; Maximum Ridge Height: 6.457 m
PSet_Revit_Other - InstallationDate: InstallationDate; SerialNumber: SerialNumber; WarrantyStartDate: WarrantyStartDate; BarCode: BarCode; AssetIdentifier: AssetIdentifier; TagNumber: TagNumber
PSet_Revit_Phasing - Phase Created: New Construction
PSet_Revit_Dimensions - Thickness: 0.457 m; Volume: 60.7472 m3; Area: 132.926 m2
Pset_RoofCommon - Reference: Basic Roof:Live Roof over Wood Joist Flat Roof; IsExternal: no; TotalArea: 132.926 m2; ProjectedArea: 135.151 m2

# IfcSlab: Basic Roof:Live Roof over Wood Joist Flat Roof, Basic Roof:Live Roof over Wood Joist Flat Roof:184483
In: Roof
PredefinedType: ROOF

# IfcSlab: Floor:127mm Slab on Grade (2)
In: Level 1
PredefinedType: FLOOR; Material: Concrete 0.127 m
PSet_Revit_Type_Construction - Default Thickness: 0.127 m; Function: 0
PSet_Revit_Type_Graphics - Coarse Scale Fill Color: 0
PSet_Revit_Type_Identity Data - Manufacturer: Manufacturer
PSet_Revit_Type_Other - AccessibilityPerformance: AccessibilityPerformance; CodePerformance: CodePerformance; Color: Color; Constituents: Constituents; Features: Features; Finish: Finish; Grade: Grade; Material: Material; ModelReference: ModelReference; NominalHeight: NominalHeight; NominalLength: NominalLength; NominalWidth: NominalWidth; ProductionYear: ProductionYear; Reference: Reference; Shape: Shape; Size: Size; SustainabilityPerformance: SustainabilityPerformance; WarrantyDescription: WarrantyDescription; WarrantyDurationLabor: WarrantyDurationLabor; WarrantyDurationParts: WarrantyDurationParts; WarrantyGuarantorLabor: WarrantyGuarantorLabor; WarrantyGuarantorParts: WarrantyGuarantorParts; ExpectedLife: ExpectedLife; ReplacementCost: ReplacementCost; AssetAccountingType: FIXED; Classification Description: Structural Floor Decks; Classification Code: 23-25 30 27 11; ModelLabel: ModelLabel
PSet_Revit_Constraints - Level: Level 1; Height Offset From Level: 0 m; Room Bounding: yes; Related to Mass: no
PSet_Revit_Structural - Structural: no
PSet_Revit_Other - InstallationDate: InstallationDate; SerialNumber: SerialNumber; WarrantyStartDate: WarrantyStartDate; BarCode: BarCode; AssetIdentifier: AssetIdentifier; TagNumber: TagNumber
PSet_Revit_Phasing - Phase Created: New Construction
PSet_Revit_Dimensions - Perimeter: 34.548 m; Thickness: 0.127 m
PSet_Revit_Analytical Model - Vertical Projection: Default
PSet_Revit_Structural Analysis - Structural Usage: 3
Pset_SlabCommon - Reference: Floor:127mm Slab on Grade; IsExternal: no; LoadBearing: yes
Name (Floor:127mm Slab on Grade:...) | Area (m2) | Volume (m3)
141232 | 64.7799 | 8.22705
143106 | 64.9064 | 8.24312

# IfcSlab: Floor:150mm Exterior Slab on Grade (2)
In: Level 1
PredefinedType: FLOOR; Material: Concrete - Cast In Situ 0.15 m
PSet_Revit_Type_Construction - Default Thickness: 0.15 m; Function: 1
PSet_Revit_Type_Graphics - Coarse Scale Fill Color: 0
PSet_Revit_Type_Identity Data - Manufacturer: Manufacturer
PSet_Revit_Type_Other - AccessibilityPerformance: AccessibilityPerformance; CodePerformance: CodePerformance; Color: Color; Constituents: Constituents; Features: Features; Finish: Finish; Grade: Grade; Material: Material; ModelReference: ModelReference; NominalHeight: NominalHeight; NominalLength: NominalLength; NominalWidth: NominalWidth; ProductionYear: ProductionYear; Reference: Reference; Shape: Shape; Size: Size; SustainabilityPerformance: SustainabilityPerformance; WarrantyDescription: WarrantyDescription; WarrantyDurationLabor: WarrantyDurationLabor; WarrantyDurationParts: WarrantyDurationParts; WarrantyGuarantorLabor: WarrantyGuarantorLabor; WarrantyGuarantorParts: WarrantyGuarantorParts; ExpectedLife: ExpectedLife; ReplacementCost: ReplacementCost; AssetAccountingType: FIXED; Classification Description: Structural Floor Decks; Classification Code: 23-25 30 27 11; ModelLabel: ModelLabel
PSet_Revit_Constraints - Level: Level 1; Height Offset From Level: 0.013 m; Room Bounding: yes; Related to Mass: no
PSet_Revit_Structural - Structural: no
PSet_Revit_Other - InstallationDate: InstallationDate; SerialNumber: SerialNumber; WarrantyStartDate: WarrantyStartDate; BarCode: BarCode; AssetIdentifier: AssetIdentifier; TagNumber: TagNumber
PSet_Revit_Phasing - Phase Created: New Construction
PSet_Revit_Dimensions - Perimeter: 20.3655 m; Area: 25.4199 m2; Volume: 3.81298 m3; Thickness: 0.15 m
PSet_Revit_Analytical Model - Vertical Projection: Default
PSet_Revit_Structural Analysis - Structural Usage: 3
Pset_SlabCommon - Reference: Floor:150mm Exterior Slab on Grade; IsExternal: no; LoadBearing: yes
Name (Floor:150mm Exterior Slab on Grade:...)
216507
216552

# IfcSlab: Floor:Finish Floor - Ceramic Tile (6)
PredefinedType: FLOOR; Material: Ceramic Tile 0.01 m, Masonry - Grout 0.003 m
PSet_Revit_Type_Construction - Default Thickness: 0.013 m; Function: 0
PSet_Revit_Type_Graphics - Coarse Scale Fill Color: 0
PSet_Revit_Type_Identity Data - Manufacturer: Manufacturer
PSet_Revit_Type_Other - AccessibilityPerformance: AccessibilityPerformance; CodePerformance: CodePerformance; Color: Color; Constituents: Constituents; Features: Features; Finish: Finish; Grade: Grade; Material: Material; ModelReference: ModelReference; NominalHeight: NominalHeight; NominalLength: NominalLength; NominalWidth: NominalWidth; ProductionYear: ProductionYear; Reference: Reference; Shape: Shape; Size: Size; SustainabilityPerformance: SustainabilityPerformance; WarrantyDescription: WarrantyDescription; WarrantyDurationLabor: WarrantyDurationLabor; WarrantyDurationParts: WarrantyDurationParts; WarrantyGuarantorLabor: WarrantyGuarantorLabor; WarrantyGuarantorParts: WarrantyGuarantorParts; ExpectedLife: ExpectedLife; ReplacementCost: ReplacementCost; AssetAccountingType: FIXED; Classification Description: Tile Flooring; Classification Code: 23-35 50 14 14; ModelLabel: ModelLabel
PSet_Revit_Structural - Structural: no
PSet_Revit_Other - InstallationDate: InstallationDate; SerialNumber: SerialNumber; WarrantyStartDate: WarrantyStartDate; BarCode: BarCode; AssetIdentifier: AssetIdentifier; TagNumber: TagNumber
PSet_Revit_Phasing - Phase Created: New Construction
PSet_Revit_Dimensions - Thickness: 0.013 m
PSet_Revit_Analytical Model - Vertical Projection: Default
PSet_Revit_Structural Analysis - Structural Usage: 3
Pset_SlabCommon - Reference: Floor:Finish Floor - Ceramic Tile; IsExternal: no; LoadBearing: yes
PSet_Revit_Constraints - Height Offset From Level: 0.013 m; Room Bounding: yes; Related to Mass: no
Name (Floor:Finish Floor - Ceramic Tile:...) | In | Perimeter (m) | Area (m2) | Volume (m3) | Level
169772 | Level 2 | 11.368 | 6.33984 | 0.0824179 | Level 2
169866 | Level 2 | 11.368 | 6.33984 | 0.0824179 | Level 2
171444 | Level 1 | 16.078 | 12.9541 | 0.168403 | Level 1
171261 | Level 1 | 7.254 | 3.16098 | 0.0410927 | Level 1
170785 | Level 1 | 16.078 | 12.9541 | 0.168403 | Level 1
171230 | Level 1 | 7.254 | 3.16098 | 0.0410927 | Level 1

# IfcSlab: Floor:Finish Floor - Wood (8)
PredefinedType: FLOOR; Material: Wood - Flooring 0.016 m, Insulation / Thermal Barriers - Semi-rigid insulation 0.003 m
PSet_Revit_Type_Identity Data - Manufacturer: Manufacturer
PSet_Revit_Type_Other - AccessibilityPerformance: AccessibilityPerformance; CodePerformance: CodePerformance; Color: Color; Constituents: Constituents; Features: Features; Finish: Finish; Grade: Grade; Material: Material; ModelReference: ModelReference; NominalHeight: NominalHeight; NominalLength: NominalLength; NominalWidth: NominalWidth; ProductionYear: ProductionYear; Reference: Reference; Shape: Shape; Size: Size; SustainabilityPerformance: SustainabilityPerformance; WarrantyDescription: WarrantyDescription; WarrantyDurationLabor: WarrantyDurationLabor; WarrantyDurationParts: WarrantyDurationParts; WarrantyGuarantorLabor: WarrantyGuarantorLabor; WarrantyGuarantorParts: WarrantyGuarantorParts; ExpectedLife: ExpectedLife; ReplacementCost: ReplacementCost; AssetAccountingType: FIXED; Classification Description: Wood Flooring; Classification Code: 23-35 50 14 11; ModelLabel: ModelLabel
PSet_Revit_Type_Construction - Default Thickness: 0.019 m; Function: 0
PSet_Revit_Type_Graphics - Coarse Scale Fill Color: 0
PSet_Revit_Structural - Structural: no
PSet_Revit_Other - InstallationDate: InstallationDate; SerialNumber: SerialNumber; WarrantyStartDate: WarrantyStartDate; BarCode: BarCode; AssetIdentifier: AssetIdentifier; TagNumber: TagNumber
PSet_Revit_Phasing - Phase Created: New Construction
PSet_Revit_Dimensions - Thickness: 0.019 m
PSet_Revit_Analytical Model - Vertical Projection: Default
PSet_Revit_Structural Analysis - Structural Usage: 3
Pset_SlabCommon - Reference: Floor:Finish Floor - Wood; IsExternal: no; LoadBearing: yes
PSet_Revit_Constraints - Height Offset From Level: 0.019 m; Room Bounding: yes; Related to Mass: no
Name (Floor:Finish Floor - Wood:...) | In | Perimeter (m) | Area (m2) | Volume (m3) | Level
171292 | Level 1 | 41.962 | 47.1501 | 0.895852 | Level 1
169093 | Level 2 | 19.914 | 22.0432 | 0.418821 | Level 2
169354 | Level 2 | 19.914 | 22.0432 | 0.418821 | Level 2
170352 | Level 1 | 41.962 | 47.1499 | 0.895848 | Level 1
169395 | Level 2 | 15.274 | 7.21087 | 0.137006 | Level 2
169701 | Level 2 | 15.274 | 7.21087 | 0.137006 | Level 2
169308 | Level 2 | 19.946 | 22.0691 | 0.419314 | Level 2
169188 | Level 2 | 19.914 | 22.0432 | 0.418821 | Level 2

# IfcSlab: Floor:Residential - Wood Joist with Subflooring (2)
In: Level 2
PredefinedType: FLOOR; Material: Wood - Sheathing - plywood 0.019 m, Wood - Dimensional Lumber 0.286 m
PSet_Revit_Type_Construction - Default Thickness: 0.305 m; Function: 0
PSet_Revit_Type_Graphics - Coarse Scale Fill Color: 0
PSet_Revit_Type_Identity Data - Manufacturer: Manufacturer
PSet_Revit_Type_Other - AccessibilityPerformance: AccessibilityPerformance; CodePerformance: CodePerformance; Color: Color; Constituents: Constituents; Features: Features; Finish: Finish; Grade: Grade; Material: Material; ModelReference: ModelReference; NominalHeight: NominalHeight; NominalLength: NominalLength; NominalWidth: NominalWidth; ProductionYear: ProductionYear; Reference: Reference; Shape: Shape; Size: Size; SustainabilityPerformance: SustainabilityPerformance; WarrantyDescription: WarrantyDescription; WarrantyDurationLabor: WarrantyDurationLabor; WarrantyDurationParts: WarrantyDurationParts; WarrantyGuarantorLabor: WarrantyGuarantorLabor; WarrantyGuarantorParts: WarrantyGuarantorParts; ExpectedLife: ExpectedLife; ReplacementCost: ReplacementCost; AssetAccountingType: FIXED; Classification Description: Structural Floor Decks; Classification Code: 23-25 30 27 11; ModelLabel: ModelLabel
PSet_Revit_Constraints - Level: Level 2; Height Offset From Level: 0 m; Room Bounding: yes; Related to Mass: no
PSet_Revit_Structural - Structural: no
PSet_Revit_Other - InstallationDate: InstallationDate; SerialNumber: SerialNumber; WarrantyStartDate: WarrantyStartDate; BarCode: BarCode; AssetIdentifier: AssetIdentifier; TagNumber: TagNumber
PSet_Revit_Phasing - Phase Created: New Construction
PSet_Revit_Dimensions - Thickness: 0.305 m
PSet_Revit_Analytical Model - Vertical Projection: Default
PSet_Revit_Structural Analysis - Structural Usage: 3
Pset_SlabCommon - Reference: Floor:Residential - Wood Joist with Subflooring; IsExternal: no; LoadBearing: yes
Name (Floor:Residential - Wood Joist with Subflooring:...) | Perimeter (m) | Area (m2) | Volume (m3)
144800 | 43.4568 | 59.229 | 18.0649
144872 | 43.3968 | 59.3337 | 18.0968

# IfcStair: Stair:Residential - 200mm Max Riser 250mm Tread (2)
In: Level 1
PSet_Revit_Type_Identity Data - Manufacturer: Manufacturer
PSet_Revit_Type_Construction - Extend Below Base: 0 m; Monolithic Stairs: no; Landing Overlap: 0.076 m; Underside of Winder: 1; Function: 0
PSet_Revit_Type_Treads - Minimum Tread Depth: 0.25 m; Tread Thickness: 0.05 m; Nosing Length: 0.01 m; Nosing Profile: M_Stair Nosing - Radius : 20mm; Apply Nosing Profile: 0
PSet_Revit_Type_Risers - Maximum Riser Height: 0.2 m; Begin with Riser: yes; End with Riser: yes; Riser Type: 1; Riser Thickness: 0.0125 m; Riser to Tread Connection: 0
PSet_Revit_Type_Stringers - Trim Stringers at Top: 1; Right Stringer: 1; Left Stringer: 1; Middle Stringers: 0; Stringer Thickness: 0.05 m; Stringer Height: 0.4 m; Open Stringer Offset: 0 m; Stringer Carriage Height: 0.152 m; Landing Carriage Height: 0.307563 m
PSet_Revit_Type_Materials and Finishes - Tread Material: Wood - Flooring; Riser Material: Wood - Flooring; Stringer Material: Wood - Dimensional Lumber
PSet_Revit_Type_Graphics - Break Symbol in Plan: yes; Text Size: 0.0082021; Text Font: Arial
PSet_Revit_Type_Other - AccessibilityPerformance: AccessibilityPerformance; CodePerformance: CodePerformance; Color: Color; Constituents: Constituents; Features: Features; Finish: Finish; Grade: Grade; Material: Material; ModelReference: ModelReference; NominalHeight: NominalHeight; NominalLength: NominalLength; NominalWidth: NominalWidth; ProductionYear: ProductionYear; Reference: Reference; Shape: Shape; Size: Size; SustainabilityPerformance: SustainabilityPerformance; WarrantyDescription: WarrantyDescription; WarrantyDurationLabor: WarrantyDurationLabor; WarrantyDurationParts: WarrantyDurationParts; WarrantyGuarantorLabor: WarrantyGuarantorLabor; WarrantyGuarantorParts: WarrantyGuarantorParts; ExpectedLife: ExpectedLife; ReplacementCost: ReplacementCost; AssetAccountingType: FIXED; Classification Description: Stairs; Classification Code: 23-30 70 21; ModelLabel: ModelLabel
PSet_Revit_Dimensions - Width: 1 m; Desired Number of Risers: 16; Actual Number of Risers: 16; Actual Riser Height: 0.19375 m; Actual Tread Depth: 0.25 m
PSet_Revit_Constraints - Base Level: Level 1; Base Offset: 0 m; Top Level: Level 2; Top Offset: 0 m
PSet_Revit_Graphics - Up text: UP; Down text: DN; Up label: yes; Up arrow: yes; Down label: yes; Down arrow: yes; Show Up arrow in all views: no
PSet_Revit_Other - InstallationDate: InstallationDate; SerialNumber: SerialNumber; WarrantyStartDate: WarrantyStartDate; BarCode: BarCode; AssetIdentifier: AssetIdentifier; TagNumber: TagNumber
PSet_Revit_Phasing - Phase Created: New Construction
Pset_StairCommon - Reference: Stair:Residential - 200mm Max Riser 250mm Tread; NumberOfRiser: 16; NumberOfTreads: 15; RiserHeight: 0.19375 m; TreadLength: 0.25 m; IsExternal: no
Name (Stair:Residential - 200mm Max Riser 250mm Tread:...)
151086
198878

# IfcStairFlight: Stair:Residential - 200mm Max Riser 250mm Tread (2)
In: Level 1
NumberOfTreads: 15; RiserHeight: 0.635663 m; TreadLength: 0.82021 m
Pset_StairFlightCommon - Reference: Stair:Residential - 200mm Max Riser 250mm Tread; NumberOfRiser: 16; NumberOfTreads: 15; RiserHeight: 0.19375 m; TreadLength: 0.25 m; NosingLength: 0.01 m; TreadLengthAtInnerSide: 0.25 m; TreadLengthAtOffset: 0.25 m; WalkingLineOffset: 0.4572 m; WaistThickness: 0.9144 m
Name (Stair:Residential - 200mm Max Riser 250mm Tread:...)
151086:1
198878:1

# IfcWall: Basic Wall:Exterior - Brick on Block:130892 (12)
PredefinedType: SOLIDWALL; Material: Masonry - Brick 0.092 m, Misc. Air Layers - Air Space 0.025 m, Insulation / Thermal Barriers - Rigid insulation 0.05 m, Masonry - Concrete Block 0.193 m, Metal - Stud Layer 0.041 m, Plasterboard 0.016 m
PSet_Revit_Type_Construction - Wrapping at Inserts: 0; Wrapping at Ends: 0; Width: 0.417 m; Function: 1
PSet_Revit_Type_Graphics - Coarse Scale Fill Color: 0
PSet_Revit_Type_Identity Data - Manufacturer: Manufacturer
PSet_Revit_Type_Other - AccessibilityPerformance: AccessibilityPerformance; CodePerformance: CodePerformance; Color: Color; Constituents: Constituents; Features: Features; Finish: Finish; Grade: Grade; Material: Material; ModelReference: ModelReference; NominalHeight: NominalHeight; NominalLength: NominalLength; NominalWidth: NominalWidth; ProductionYear: ProductionYear; Reference: Reference; Shape: Shape; Size: Size; SustainabilityPerformance: SustainabilityPerformance; WarrantyDescription: WarrantyDescription; WarrantyDurationLabor: WarrantyDurationLabor; WarrantyDurationParts: WarrantyDurationParts; WarrantyGuarantorLabor: WarrantyGuarantorLabor; WarrantyGuarantorParts: WarrantyGuarantorParts; ExpectedLife: ExpectedLife; ReplacementCost: ReplacementCost; AssetAccountingType: FIXED; Classification Description: Masonry Structural Walls; Classification Code: 23-25 30 24 14; ModelLabel: ModelLabel
PSet_Revit_Other - InstallationDate: InstallationDate; SerialNumber: SerialNumber; WarrantyStartDate: WarrantyStartDate; BarCode: BarCode; AssetIdentifier: AssetIdentifier; TagNumber: TagNumber
PSet_Revit_Phasing - Phase Created: New Construction
PSet_Revit_Structural - Structural Usage: 0
PSet_Revit_Constraints - Location Line: 2; Base Offset: 0 m; Base is Attached: no; Base Extension Distance: 0 m; Top is Attached: no; Top Extension Distance: 0 m; Room Bounding: yes; Related to Mass: no
Pset_WallCommon - Reference: Basic Wall:Exterior - Brick on Block; IsExternal: yes; LoadBearing: no; ThermalTransmittance: 0.35
Name (Basic Wall:Exterior - Brick on Block:...) | In | Length (m) | Area (m2) | Volume (m3) | Base Constraint | Top Constraint | Unconnected Height (m) | Top Offset (m)
143534 | Level 2 | 8.383 | 16.9071 | 6.546 | Level 2 | Up to level: Roof | 2.9 | 0
143590 | Level 2 | 17.383 | 41.3571 | 16.7416 | Level 2 | Up to level: Roof | 2.9 | 0
184944 | Roof | 8.383 | 5.3592 | 2.23479 | Roof | Up to level: Roof | 0.609 | 0.609
185014 | Roof | 17.383 | 10.5862 | 4.41446 | Roof | Up to level: Roof | 0.609 | 0.609
185064 | Roof | 8.383 | 5.10525 | 2.12889 | Roof | Up to level: Roof | 0.609 | 0.609
185101 | Roof | 17.383 | 10.3323 | 4.30857 | Roof | Up to level: Roof | 0.609 | 0.609
138062 | Level 1 | 8.383 | 13.6118 | 5.67614 | Level 1 | Up to level: Level 2 | 3.1 | 0
138310 | Level 1 | 17.383 | 48.4321 | 20.1962 | Level 1 | Up to level: Level 2 | 3.1 | 0
143410 | Level 2 | 8.383 | 16.9071 | 6.546 | Level 2 | Up to level: Roof | 2.9 | 0
138157 | Level 1 | 17.383 | 49.7248 | 20.7352 | Level 1 | Up to level: Level 2 | 3.1 | 0
138237 | Level 1 | 8.383 | 12.3191 | 5.13708 | Level 1 | Up to level: Level 2 | 3.1 | 0
143478 | Level 2 | 17.383 | 41.3571 | 16.7416 | Level 2 | Up to level: Roof | 2.9 | 0

# IfcWall: Basic Wall:Foundation - Concrete (417mm):128676 (4)
In: T/FDN
PredefinedType: SOLIDWALL; Material: Concrete - Cast In Situ 0.417 m
PSet_Revit_Type_Construction - Wrapping at Inserts: 0; Wrapping at Ends: 0; Width: 0.417 m; Function: 2
PSet_Revit_Type_Graphics - Coarse Scale Fill Pattern: Concrete; Coarse Scale Fill Color: 0
PSet_Revit_Type_Identity Data - Manufacturer: Manufacturer
PSet_Revit_Type_Other - AccessibilityPerformance: AccessibilityPerformance; CodePerformance: CodePerformance; Color: Color; Constituents: Constituents; Features: Features; Finish: Finish; Grade: Grade; Material: Material; ModelReference: ModelReference; NominalHeight: NominalHeight; NominalLength: NominalLength; NominalWidth: NominalWidth; ProductionYear: ProductionYear; Reference: Reference; Shape: Shape; Size: Size; SustainabilityPerformance: SustainabilityPerformance; WarrantyDescription: WarrantyDescription; WarrantyDurationLabor: WarrantyDurationLabor; WarrantyDurationParts: WarrantyDurationParts; WarrantyGuarantorLabor: WarrantyGuarantorLabor; WarrantyGuarantorParts: WarrantyGuarantorParts; ExpectedLife: ExpectedLife; ReplacementCost: ReplacementCost; AssetAccountingType: FIXED; Classification Description: Concrete Structural Walls; Classification Code: 23-25 30 24 11; ModelLabel: ModelLabel
PSet_Revit_Constraints - Location Line: 3; Base Constraint: T/FDN; Base Offset: 0 m; Base is Attached: no; Base Extension Distance: 0 m; Top Constraint: Up to level: Level 1; Unconnected Height: 1.25 m; Top Offset: 0 m; Top is Attached: no; Top Extension Distance: 0 m; Room Bounding: yes; Related to Mass: no
PSet_Revit_Other - InstallationDate: InstallationDate; SerialNumber: SerialNumber; WarrantyStartDate: WarrantyStartDate; BarCode: BarCode; AssetIdentifier: AssetIdentifier; TagNumber: TagNumber
PSet_Revit_Phasing - Phase Created: New Construction
PSet_Revit_Structural - Rebar Cover - Exterior Face: Rebar Cover 1 <0.025>; Rebar Cover - Interior Face: Rebar Cover 1 <0.025>; Rebar Cover - Other Faces: Rebar Cover 1 <0.025>; Structural Usage: 1
PSet_Revit_Analytical Model - Enable Analytical Model: yes
Pset_WallCommon - Reference: Basic Wall:Foundation - Concrete (417mm); IsExternal: yes; LoadBearing: yes; ThermalTransmittance: 0.35
Name (Basic Wall:Foundation - Concrete (417mm):...) | Length (m) | Area (m2) | Volume (m3)
140479 | 8.383 | 11 | 4.587
140602 | 17.383 | 21.2075 | 8.84353
140520 | 17.383 | 21.7287 | 9.06089
140554 | 8.383 | 10.4787 | 4.36964

# IfcWall: Basic Wall:Foundation - Concrete (435mm):207146 (3)
In: T/FDN
PredefinedType: SOLIDWALL; Material: Concrete - Cast In Situ 0.435 m
PSet_Revit_Type_Construction - Wrapping at Inserts: 0; Wrapping at Ends: 0; Width: 0.435 m; Function: 2
PSet_Revit_Type_Graphics - Coarse Scale Fill Pattern: Concrete; Coarse Scale Fill Color: 0
PSet_Revit_Type_Identity Data - Manufacturer: Manufacturer
PSet_Revit_Type_Other - AccessibilityPerformance: AccessibilityPerformance; CodePerformance: CodePerformance; Color: Color; Constituents: Constituents; Features: Features; Finish: Finish; Grade: Grade; Material: Material; ModelReference: ModelReference; NominalHeight: NominalHeight; NominalLength: NominalLength; NominalWidth: NominalWidth; ProductionYear: ProductionYear; Reference: Reference; Shape: Shape; Size: Size; SustainabilityPerformance: SustainabilityPerformance; WarrantyDescription: WarrantyDescription; WarrantyDurationLabor: WarrantyDurationLabor; WarrantyDurationParts: WarrantyDurationParts; WarrantyGuarantorLabor: WarrantyGuarantorLabor; WarrantyGuarantorParts: WarrantyGuarantorParts; ExpectedLife: ExpectedLife; ReplacementCost: ReplacementCost; AssetAccountingType: FIXED; Classification Description: Concrete Structural Walls; Classification Code: 23-25 30 24 11; ModelLabel: ModelLabel
PSet_Revit_Constraints - Location Line: 0; Base Constraint: T/FDN; Base Offset: 0 m; Base is Attached: no; Base Extension Distance: 0 m; Top Constraint: Up to level: Level 1; Top is Attached: no; Top Extension Distance: 0 m; Room Bounding: yes; Related to Mass: no
PSet_Revit_Other - InstallationDate: InstallationDate; SerialNumber: SerialNumber; WarrantyStartDate: WarrantyStartDate; BarCode: BarCode; AssetIdentifier: AssetIdentifier; TagNumber: TagNumber
PSet_Revit_Phasing - Phase Created: New Construction
PSet_Revit_Structural - Rebar Cover - Exterior Face: Rebar Cover 1 <0.025>; Rebar Cover - Interior Face: Rebar Cover 1 <0.025>; Rebar Cover - Other Faces: Rebar Cover 1 <0.025>; Structural Usage: 1
PSet_Revit_Analytical Model - Enable Analytical Model: yes
Pset_WallCommon - Reference: Basic Wall:Foundation - Concrete (435mm); IsExternal: yes; LoadBearing: yes; ThermalTransmittance: 0.35
Name (Basic Wall:Foundation - Concrete (435mm):...) | Unconnected Height (m) | Top Offset (m) | Length (m) | Area (m2) | Volume (m3)
140913 | 1.25 | 0 | 4.1915 | 5.25062 | 2.28402
141018 | 1.123 | -0.127 | 2.2 | 1.9821 | 0.862211
140987 | 1.25 | 0 | 4.1915 | 5.25062 | 2.28402

# IfcWall: Basic Wall:Interior - Furring (152 mm Stud):187795 (6)
PredefinedType: SOLIDWALL; Material: Metal - Stud Layer 0.136 m, Plasterboard 0.016 m
PSet_Revit_Type_Construction - Wrapping at Inserts: 0; Wrapping at Ends: 0; Width: 0.152 m; Function: 0
PSet_Revit_Type_Graphics - Coarse Scale Fill Color: 0
PSet_Revit_Type_Identity Data - Manufacturer: Manufacturer
PSet_Revit_Type_Other - AccessibilityPerformance: AccessibilityPerformance; CodePerformance: CodePerformance; Color: Color; Constituents: Constituents; Features: Features; Finish: Finish; Grade: Grade; Material: Material; ModelReference: ModelReference; NominalHeight: NominalHeight; NominalLength: NominalLength; NominalWidth: NominalWidth; ProductionYear: ProductionYear; Reference: Reference; Shape: Shape; Size: Size; SustainabilityPerformance: SustainabilityPerformance; WarrantyDescription: WarrantyDescription; WarrantyDurationLabor: WarrantyDurationLabor; WarrantyDurationParts: WarrantyDurationParts; WarrantyGuarantorLabor: WarrantyGuarantorLabor; WarrantyGuarantorParts: WarrantyGuarantorParts; ExpectedLife: ExpectedLife; ReplacementCost: ReplacementCost; AssetAccountingType: FIXED; Classification Description: Metal-Framed Gypsum Board Fixed Partitions; Classification Code: 23-25 40 11 11 11; ModelLabel: ModelLabel
PSet_Revit_Constraints - Location Line: 2; Base Offset: 0 m; Base is Attached: no; Base Extension Distance: 0 m; Top Extension Distance: 0 m; Room Bounding: yes; Related to Mass: no
PSet_Revit_Other - InstallationDate: InstallationDate; SerialNumber: SerialNumber; WarrantyStartDate: WarrantyStartDate; BarCode: BarCode; AssetIdentifier: AssetIdentifier; TagNumber: TagNumber
PSet_Revit_Phasing - Phase Created: New Construction
PSet_Revit_Structural - Structural Usage: 0
Pset_WallCommon - Reference: Basic Wall:Interior - Furring (152 mm Stud); IsExternal: no; LoadBearing: no; ThermalTransmittance: 0.35
Name (Basic Wall:Interior - Furring (152 mm Stud):...) | In | Base Constraint | Unconnected Height (m) | Top Offset (m) | Top is Attached | Length (m) | Area (m2) | Volume (m3) | Top Constraint
189074 | Level 1 | Level 1 | 3.1 | 0 | yes | 4.4855 | 12.1666 | 1.84933
189901 | Level 1 | Level 1 | 3.1 | 0 | no | 2.508 | 6.6433 | 1.00978
190774 | Level 1 | Level 1 | 2.795 | -0.305 | no | 2.508 | 6.41453 | 0.975008 | Up to level: Level 2
190933 | Level 1 | Level 1 | 2.795 | -0.305 | no | 4.4855 | 11.7418 | 1.78475 | Up to level: Level 2
194166 | Level 2 | Level 2 | 2.595 | -0.305 | no | 4.314 | 10.7952 | 1.64087 | Up to level: Roof
193247 | Level 2 | Level 2 | 2.595 | -0.305 | no | 4.314 | 10.7952 | 1.64087 | Up to level: Roof

# IfcWall: Basic Wall:Interior - Furring (38 mm Stud):128404 (8)
In: Level 2
PredefinedType: SOLIDWALL; Material: Metal - Stud Layer 0.038 m, Plasterboard 0.016 m
PSet_Revit_Type_Construction - Wrapping at Inserts: 0; Wrapping at Ends: 0; Width: 0.054 m; Function: 0
PSet_Revit_Type_Graphics - Coarse Scale Fill Color: 0
PSet_Revit_Type_Other - Classification Description: Metal-Framed Gypsum Board Fixed Partitions; Classification Code: 23-25 40 11 11 11
PSet_Revit_Constraints - Location Line: 3; Base Constraint: Level 2; Base Offset: 2.612 m; Base is Attached: no; Base Extension Distance: 0 m; Top Constraint: Up to level: Roof; Unconnected Height: 0.288 m; Top Offset: 0 m; Top is Attached: no; Top Extension Distance: 0 m; Room Bounding: yes; Related to Mass: no
PSet_Revit_Other - InstallationDate: InstallationDate; SerialNumber: SerialNumber; WarrantyStartDate: WarrantyStartDate; BarCode: BarCode; AssetIdentifier: AssetIdentifier; TagNumber: TagNumber
PSet_Revit_Phasing - Phase Created: New Construction
PSet_Revit_Structural - Structural Usage: 0
Pset_WallCommon - Reference: Basic Wall:Interior - Furring (38 mm Stud); IsExternal: no; LoadBearing: no; ThermalTransmittance: 0.35
Name (Basic Wall:Interior - Furring (38 mm Stud):...) | Length (m) | Area (m2) | Volume (m3)
217414 | 1.0831 | 0.311933 | 0.0168444
217417 | 1.1351 | 0.326909 | 0.0176531
217577 | 1.0831 | 0.311933 | 0.0168444
217580 | 1.1351 | 0.326909 | 0.0176531
217415 | 1.1351 | 0.326909 | 0.0176531
217416 | 1.0831 | 0.311933 | 0.0168444
217578 | 1.1351 | 0.326909 | 0.0176531
217579 | 1.0831 | 0.311933 | 0.0168444

# IfcWall: Basic Wall:Interior - Partition (92mm Stud):128360 (18)
PredefinedType: SOLIDWALL; Material: Plasterboard 0.016 m, Metal - Stud Layer 0.092 m, Plasterboard 0.016 m
PSet_Revit_Type_Construction - Wrapping at Inserts: 0; Wrapping at Ends: 2; Width: 0.124 m; Function: 0
PSet_Revit_Type_Graphics - Coarse Scale Fill Color: 0
PSet_Revit_Type_Identity Data - Manufacturer: Manufacturer
PSet_Revit_Type_Other - AccessibilityPerformance: AccessibilityPerformance; CodePerformance: CodePerformance; Color: Color; Constituents: Constituents; Features: Features; Finish: Finish; Grade: Grade; Material: Material; ModelReference: ModelReference; NominalHeight: NominalHeight; NominalLength: NominalLength; NominalWidth: NominalWidth; ProductionYear: ProductionYear; Reference: Reference; Shape: Shape; Size: Size; SustainabilityPerformance: SustainabilityPerformance; WarrantyDescription: WarrantyDescription; WarrantyDurationLabor: WarrantyDurationLabor; WarrantyDurationParts: WarrantyDurationParts; WarrantyGuarantorLabor: WarrantyGuarantorLabor; WarrantyGuarantorParts: WarrantyGuarantorParts; ExpectedLife: ExpectedLife; ReplacementCost: ReplacementCost; AssetAccountingType: FIXED; Classification Description: Metal-Framed Gypsum Board Fixed Partitions; Classification Code: 23-25 40 11 11 11; ModelLabel: ModelLabel
PSet_Revit_Constraints - Base is Attached: no; Base Extension Distance: 0 m; Top is Attached: no; Top Extension Distance: 0 m; Room Bounding: yes; Related to Mass: no
PSet_Revit_Other - InstallationDate: InstallationDate; SerialNumber: SerialNumber; WarrantyStartDate: WarrantyStartDate; BarCode: BarCode; AssetIdentifier: AssetIdentifier; TagNumber: TagNumber
PSet_Revit_Phasing - Phase Created: New Construction
PSet_Revit_Structural - Structural Usage: 0
Pset_WallCommon - Reference: Basic Wall:Interior - Partition (92mm Stud); IsExternal: no; LoadBearing: no; ThermalTransmittance: 0.35
Name (Basic Wall:Interior - Partition (92mm Stud):...) | In | Location Line | Base Constraint | Base Offset (m) | Top Constraint | Unconnected Height (m) | Top Offset (m) | Length (m) | Area (m2) | Volume (m3)
143856 | Level 1 | 3 | Level 2 | -0.488 | Up to level: Roof | 3.388 | 0 | 2.2355 | 5.32188 | 0.659914
143921 | Level 2 | 3 | Level 2 | 0 | Up to level: Roof | 2.9 | 0 | 5.424 | 13.974 | 1.73277
143960 | Level 2 | 3 | Level 2 | 0 | Up to level: Roof | 2.9 | 0 | 2.2355 | 3.94285 | 0.488914
144518 | Level 1 | 3 | Level 2 | -0.488 | Up to level: Roof | 3.388 | 0 | 2.2355 | 5.32188 | 0.659914
144586 | Level 2 | 3 | Level 2 | 0 | Up to level: Roof | 2.9 | 0 | 5.424 | 13.974 | 1.73277
144633 | Level 2 | 3 | Level 2 | 0 | Up to level: Roof | 2.9 | 0 | 2.2355 | 3.94285 | 0.488914
190140 | Level 1 | 3 | Level 1 | 0 | Up to level: Level 2 | 2.795 | -0.305 | 1.594 | 4.06952 | 0.50462
139682 | Level 1 | 3 | Level 1 | 0 | Up to level: Level 2 | 2.795 | -0.305 | 3.195 | 6.61302 | 0.820014
139783 | Level 1 | 3 | Level 1 | 0 | Up to level: Level 2 | 2.795 | -0.305 | 1.594 | 4.06952 | 0.50462
139143 | Level 1 | 3 | Level 1 | 0 | Up to level: Level 2 | 2.795 | -0.305 | 3.195 | 6.61302 | 0.820014
138584 | Level 1 | 2 | Level 1 | 0 | Up to level: Level 2 | 2.795 | -0.305 | 3.7915 | 10.0145 | 1.2418
139939 | Level 1 | 3 | Level 1 | 0 | Up to level: Level 2 | 2.795 | -0.305 | 3.7915 | 10.0145 | 1.2418
204493 | Level 1 | 3 | Level 2 | -0.488 | Up to level: Level 2 | 0.488 | 0 | 3.812 | 1.6958 | 0.210279
204300 | Level 1 | 3 | Level 2 | -0.488 | Up to level: Level 2 | 0.488 | 0 | 3.812 | 1.6958 | 0.210279
144301 | Level 2 | 2 | Level 2 | 0 | Up to level: Roof | 2.9 | 0 | 1.956 | 4.6951 | 0.582192
144684 | Level 2 | 2 | Level 2 | 0 | Up to level: Roof | 2.9 | 0 | 1.956 | 4.6951 | 0.582192
203998 | Level 2 | 2 | Level 2 | 0 | Up to level: Roof | 2.9 | 0 | 1.662 | 2.87122 | 0.356031
203347 | Level 2 | 3 | Level 2 | 0 | Up to level: Roof | 2.9 | 0 | 1.662 | 2.87122 | 0.356031

# IfcWall: Basic Wall:Interior - Plumbing (152mm Stud):128382 (2)
In: Level 2
PredefinedType: SOLIDWALL; Material: Plasterboard 0.016 m, Metal - Stud Layer 0.152 m, Plasterboard 0.016 m
PSet_Revit_Type_Construction - Wrapping at Inserts: 0; Wrapping at Ends: 0; Width: 0.184 m; Function: 0
PSet_Revit_Type_Graphics - Coarse Scale Fill Color: 0
PSet_Revit_Type_Identity Data - Manufacturer: Manufacturer
PSet_Revit_Type_Other - AccessibilityPerformance: AccessibilityPerformance; CodePerformance: CodePerformance; Color: Color; Constituents: Constituents; Features: Features; Finish: Finish; Grade: Grade; Material: Material; ModelReference: ModelReference; NominalHeight: NominalHeight; NominalLength: NominalLength; NominalWidth: NominalWidth; ProductionYear: ProductionYear; Reference: Reference; Shape: Shape; Size: Size; SustainabilityPerformance: SustainabilityPerformance; WarrantyDescription: WarrantyDescription; WarrantyDurationLabor: WarrantyDurationLabor; WarrantyDurationParts: WarrantyDurationParts; WarrantyGuarantorLabor: WarrantyGuarantorLabor; WarrantyGuarantorParts: WarrantyGuarantorParts; ExpectedLife: ExpectedLife; ReplacementCost: ReplacementCost; AssetAccountingType: FIXED; Classification Description: Metal-Framed Gypsum Board Fixed Partitions; Classification Code: 23-25 40 11 11 11; ModelLabel: ModelLabel
PSet_Revit_Constraints - Location Line: 2; Base Constraint: Level 2; Base Offset: 0 m; Base is Attached: no; Base Extension Distance: 0 m; Top Constraint: Up to level: Roof; Unconnected Height: 2.9 m; Top Offset: 0 m; Top is Attached: no; Top Extension Distance: 0 m; Room Bounding: yes; Related to Mass: no
PSet_Revit_Other - InstallationDate: InstallationDate; SerialNumber: SerialNumber; WarrantyStartDate: WarrantyStartDate; BarCode: BarCode; AssetIdentifier: AssetIdentifier; TagNumber: TagNumber
PSet_Revit_Phasing - Phase Created: New Construction
PSet_Revit_Structural - Structural Usage: 0
PSet_Revit_Dimensions - Length: 1.956 m; Area: 4.6951 m2; Volume: 0.863898 m3
Pset_WallCommon - Reference: Basic Wall:Interior - Plumbing (152mm Stud); IsExternal: no; LoadBearing: no; ThermalTransmittance: 0.35
Name (Basic Wall:Interior - Plumbing (152mm Stud):...)
144783
144138

# IfcWall: Basic Wall:Party Wall - CMU Residential Unit Dimising Wall:128555 (4)
PredefinedType: SOLIDWALL; Material: Plasterboard 0.016 m, Metal - Stud Layer 0.041 m, Masonry - Concrete Block 0.193 m, Misc. Air Layers - Air Space 0.05 m, Masonry - Concrete Block 0.193 m, Metal - Stud Layer 0.041 m, Plasterboard 0.016 m
PSet_Revit_Type_Construction - Wrapping at Inserts: 0; Wrapping at Ends: 0; Width: 0.55 m; Function: 5
PSet_Revit_Type_Graphics - Coarse Scale Fill Color: 0
PSet_Revit_Type_Identity Data - Manufacturer: Manufacturer
PSet_Revit_Type_Other - AccessibilityPerformance: AccessibilityPerformance; CodePerformance: CodePerformance; Color: Color; Constituents: Constituents; Features: Features; Finish: Finish; Grade: Grade; Material: Material; ModelReference: ModelReference; NominalHeight: NominalHeight; NominalLength: NominalLength; NominalWidth: NominalWidth; ProductionYear: ProductionYear; Reference: Reference; Shape: Shape; Size: Size; SustainabilityPerformance: SustainabilityPerformance; WarrantyDescription: WarrantyDescription; WarrantyDurationLabor: WarrantyDurationLabor; WarrantyDurationParts: WarrantyDurationParts; WarrantyGuarantorLabor: WarrantyGuarantorLabor; WarrantyGuarantorParts: WarrantyGuarantorParts; ExpectedLife: ExpectedLife; ReplacementCost: ReplacementCost; AssetAccountingType: FIXED; Classification Description: Masonry Structural Walls; Classification Code: 23-25 30 24 14; ModelLabel: ModelLabel
PSet_Revit_Constraints - Location Line: 0; Base Offset: 0 m; Base is Attached: no; Base Extension Distance: 0 m; Top is Attached: no; Top Extension Distance: 0 m; Room Bounding: yes; Related to Mass: no
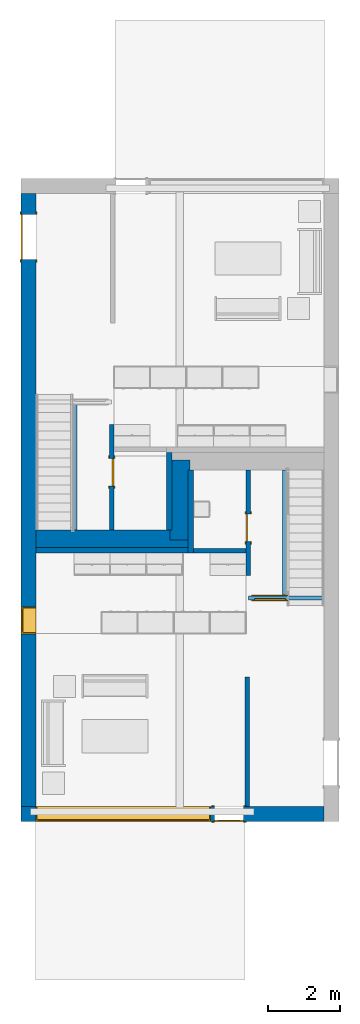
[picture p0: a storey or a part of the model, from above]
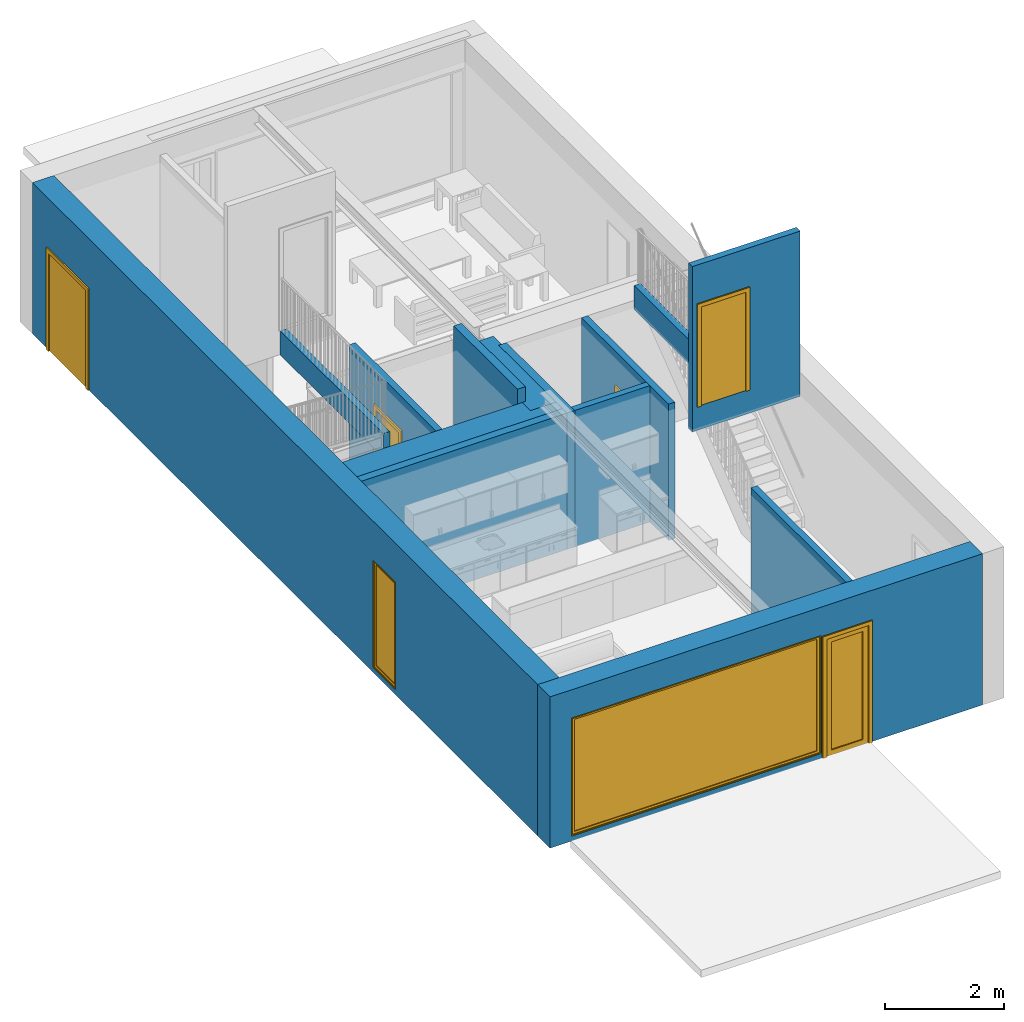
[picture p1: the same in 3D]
Properties of the parts of a building model (IFC4), part 3 of 3

# IfcWall: Basic Wall:Party Wall - CMU Residential Unit Dimising Wall:128555 (4)
PSet_Revit_Other - InstallationDate: InstallationDate; SerialNumber: SerialNumber; WarrantyStartDate: WarrantyStartDate; BarCode: BarCode; AssetIdentifier: AssetIdentifier; TagNumber: TagNumber
PSet_Revit_Phasing - Phase Created: New Construction
PSet_Revit_Structural - Structural Usage: 0
Pset_WallCommon - Reference: Basic Wall:Party Wall - CMU Residential Unit Dimising Wall; IsExternal: yes; LoadBearing: no; ThermalTransmittance: 0.35
Name (Basic Wall:Party Wall - CMU Residential Unit Dimising Wall:...) | In | Base Constraint | Top Constraint | Unconnected Height (m) | Top Offset (m) | Length (m) | Area (m2) | Volume (m3)
139234 | Level 1 | Level 1 | Up to level: Level 2 | 2.795 | -0.305 | 4.1915 | 11.7418 | 5.7887
139347 | Level 1 | Level 1 | Up to level: Level 2 | 2.795 | -0.305 | 4.1915 | 11.7418 | 5.7887
139374 | Level 1 | Level 1 | Up to level: Level 2 | 2.795 | -0.305 | 2.2 |  | 2.01072
143239 | Level 2 | Level 2 | Up to level: Roof | 2.9 | 0 | 17.383 | 38.4062 | 25.8301

# IfcWindow: 1180 x 1170mm (2)
In: Roof
Type - PredefinedType: WINDOW; ParameterTakesPrecedence: no
OverallHeight: 0.6348 m; OverallWidth: 1.17254 m
PSet_Revit_Type_Materials and Finishes - Sash Material: Metal - Bronze, Light Brush; Glass Pane Material: Glass; Frame Material: Metal - Bronze, Light Brush
PSet_Revit_Type_Dimensions - Height: 1.17 m; Width: 1.118 m
PSet_Revit_Type_Identity Data - Manufacturer: Manufacturer; Type Mark: 36; OmniClass Number: 23.30.20.21.14; OmniClass Title: Roof Windows
PSet_Revit_Type_Construction - Construction Type: Construction Type
PSet_Revit_Type_Other - AccessibilityPerformance: AccessibilityPerformance; CodePerformance: CodePerformance; ConfigurationType: ConfigurationType; ConstructionType: ConstructionType; FireRating: FireRating; GlazingAreaFraction: GlazingAreaFraction; OperationType: OperationType; Area: Area; Color: Color; Constituents: Constituents; Features: Features; Finish: Finish; Grade: Grade; Material: Material; ModelReference: ModelReference; NominalHeight: NominalHeight; NominalLength: NominalLength; NominalWidth: NominalWidth; ProductionYear: ProductionYear; Reference: Reference; Shape: Shape; Size: Size; SustainabilityPerformance: SustainabilityPerformance; WarrantyDescription: WarrantyDescription; WarrantyDurationLabor: WarrantyDurationLabor; WarrantyDurationParts: WarrantyDurationParts; WarrantyGuarantorLabor: WarrantyGuarantorLabor; WarrantyGuarantorParts: WarrantyGuarantorParts; ExpectedLife: ExpectedLife; ReplacementCost: ReplacementCost; AssetAccountingType: FIXED; ModelLabel: ModelLabel
PSet_Revit_Constraints - Level: Roof; Moves With Nearby Elements: no
PSet_Revit_Other - InstallationDate: InstallationDate; SerialNumber: SerialNumber; WarrantyStartDate: WarrantyStartDate; BarCode: BarCode; AssetIdentifier: AssetIdentifier; TagNumber: TagNumber
PSet_Revit_Phasing - Phase Created: New Construction
Pset_WindowCommon - Reference: M_Skylight:1180 x 1170mm; IsExternal: no; FireRating: FireRating
Name (M_Skylight:1180 x 1170mm:1180 x 1170mm:...) | Mark
185337 | 33
185718 | 34

# IfcWindow: 2800mm x 2410mm (4)
In: Level 2
Type - PredefinedType: WINDOW; ParameterTakesPrecedence: no
OverallHeight: 2.41 m; OverallWidth: 2.8 m
PSet_Revit_Type_Materials and Finishes - Frame Exterior Material: Sash; Frame Interior Material: Sash; Glass Pane Material: Glass; Sash: Sash
PSet_Revit_Type_Dimensions - Height: 2.41 m; Default Sill Height: 0.1 m; Width: 2.8 m; Window Inset: 0.019 m
PSet_Revit_Type_Construction - Wall Closure: 0; Construction Type: Construction Type
PSet_Revit_Type_Identity Data - Manufacturer: Manufacturer; Type Mark: 01; OmniClass Number: 23.30.20.17.11; OmniClass Title: Fixed Windows
PSet_Revit_Type_Other - AccessibilityPerformance: AccessibilityPerformance; CodePerformance: CodePerformance; ConfigurationType: ConfigurationType; ConstructionType: ConstructionType; FireRating: FireRating; GlazingAreaFraction: GlazingAreaFraction; OperationType: OperationType; Area: Area; Color: Color; Constituents: Constituents; Features: Features; Finish: Finish; Grade: Grade; Material: Material; ModelReference: ModelReference; NominalHeight: NominalHeight; NominalLength: NominalLength; NominalWidth: NominalWidth; ProductionYear: ProductionYear; Reference: Reference; Shape: Shape; Size: Size; SustainabilityPerformance: SustainabilityPerformance; WarrantyDescription: WarrantyDescription; WarrantyDurationLabor: WarrantyDurationLabor; WarrantyDurationParts: WarrantyDurationParts; WarrantyGuarantorLabor: WarrantyGuarantorLabor; WarrantyGuarantorParts: WarrantyGuarantorParts; ExpectedLife: ExpectedLife; ReplacementCost: ReplacementCost; AssetAccountingType: FIXED; ModelLabel: ModelLabel
PSet_Revit_Constraints - Level: Level 2; Sill Height: 0.1 m
PSet_Revit_Other - Head Height: 2.51 m; InstallationDate: InstallationDate; SerialNumber: SerialNumber; WarrantyStartDate: WarrantyStartDate; BarCode: BarCode; AssetIdentifier: AssetIdentifier; TagNumber: TagNumber
PSet_Revit_Phasing - Phase Created: New Construction
Pset_WindowCommon - Reference: M_Fixed:2800mm x 2410mm; IsExternal: yes; FireRating: FireRating
Name (M_Fixed:2800mm x 2410mm:2800mm x 2410mm:...) | Mark
147686 | 14
180318 | 22
181096 | 26
149278 | 18

# IfcWindow: 4835mm x 2420mm (2)
In: Level 1
Type - PredefinedType: WINDOW; ParameterTakesPrecedence: no
OverallHeight: 2.42 m; OverallWidth: 4.835 m
PSet_Revit_Type_Materials and Finishes - Frame Exterior Material: Sash; Frame Interior Material: Sash; Glass Pane Material: Glass; Sash: Sash
PSet_Revit_Type_Dimensions - Height: 2.42 m; Default Sill Height: 0.1 m; Width: 4.835 m; Window Inset: 0.019 m
PSet_Revit_Type_Construction - Wall Closure: 0; Construction Type: Construction Type
PSet_Revit_Type_Identity Data - Manufacturer: Manufacturer; Type Mark: 05; OmniClass Number: 23.30.20.17.11; OmniClass Title: Fixed Windows
PSet_Revit_Type_Other - AccessibilityPerformance: AccessibilityPerformance; CodePerformance: CodePerformance; ConfigurationType: ConfigurationType; ConstructionType: ConstructionType; FireRating: FireRating; GlazingAreaFraction: GlazingAreaFraction; OperationType: OperationType; Area: Area; Color: Color; Constituents: Constituents; Features: Features; Finish: Finish; Grade: Grade; Material: Material; ModelReference: ModelReference; NominalHeight: NominalHeight; NominalLength: NominalLength; NominalWidth: NominalWidth; ProductionYear: ProductionYear; Reference: Reference; Shape: Shape; Size: Size; SustainabilityPerformance: SustainabilityPerformance; WarrantyDescription: WarrantyDescription; WarrantyDurationLabor: WarrantyDurationLabor; WarrantyDurationParts: WarrantyDurationParts; WarrantyGuarantorLabor: WarrantyGuarantorLabor; WarrantyGuarantorParts: WarrantyGuarantorParts; ExpectedLife: ExpectedLife; ReplacementCost: ReplacementCost; AssetAccountingType: FIXED; ModelLabel: ModelLabel
PSet_Revit_Constraints - Level: Level 1; Sill Height: 0.1 m
PSet_Revit_Other - Head Height: 2.52 m; InstallationDate: InstallationDate; SerialNumber: SerialNumber; WarrantyStartDate: WarrantyStartDate; BarCode: BarCode; AssetIdentifier: AssetIdentifier; TagNumber: TagNumber
PSet_Revit_Phasing - Phase Created: New Construction
Pset_WindowCommon - Reference: M_Fixed:4835mm x 2420mm; IsExternal: yes; FireRating: FireRating
Name (M_Fixed:4835mm x 2420mm:4835mm x 2420mm:...) | Mark
145788 | 9
146016 | 10

# IfcWindow: 750mm x 2200mm (4)
Type - PredefinedType: WINDOW; ParameterTakesPrecedence: no
OverallHeight: 2.2 m; OverallWidth: 0.75 m
PSet_Revit_Type_Materials and Finishes - Frame Exterior Material: Sash; Frame Interior Material: Sash; Glass Pane Material: Glass; Sash: Sash
PSet_Revit_Type_Dimensions - Height: 2.2 m; Default Sill Height: 0.1 m; Width: 0.75 m; Window Inset: 0.019 m
PSet_Revit_Type_Construction - Wall Closure: 0; Construction Type: Construction Type
PSet_Revit_Type_Identity Data - Manufacturer: Manufacturer; Type Mark: 04; OmniClass Number: 23.30.20.17.11; OmniClass Title: Fixed Windows
PSet_Revit_Type_Other - AccessibilityPerformance: AccessibilityPerformance; CodePerformance: CodePerformance; ConfigurationType: ConfigurationType; ConstructionType: ConstructionType; FireRating: FireRating; GlazingAreaFraction: GlazingAreaFraction; OperationType: OperationType; Area: Area; Color: Color; Constituents: Constituents; Features: Features; Finish: Finish; Grade: Grade; Material: Material; ModelReference: ModelReference; NominalHeight: NominalHeight; NominalLength: NominalLength; NominalWidth: NominalWidth; ProductionYear: ProductionYear; Reference: Reference; Shape: Shape; Size: Size; SustainabilityPerformance: SustainabilityPerformance; WarrantyDescription: WarrantyDescription; WarrantyDurationLabor: WarrantyDurationLabor; WarrantyDurationParts: WarrantyDurationParts; WarrantyGuarantorLabor: WarrantyGuarantorLabor; WarrantyGuarantorParts: WarrantyGuarantorParts; ExpectedLife: ExpectedLife; ReplacementCost: ReplacementCost; AssetAccountingType: FIXED; ModelLabel: ModelLabel
PSet_Revit_Constraints - Sill Height: 0.1 m
PSet_Revit_Other - Head Height: 2.3 m; InstallationDate: InstallationDate; SerialNumber: SerialNumber; WarrantyStartDate: WarrantyStartDate; BarCode: BarCode; AssetIdentifier: AssetIdentifier; TagNumber: TagNumber
PSet_Revit_Phasing - Phase Created: New Construction
Pset_WindowCommon - Reference: M_Fixed:750mm x 2200mm; IsExternal: yes; FireRating: FireRating
Name (M_Fixed:750mm x 2200mm:750mm x 2200mm:...) | In | Level | Mark
182101 | Level 2 | Level 2 | 32
146885 | Level 1 | Level 1 | 12
181930 | Level 2 | Level 2 | 31
147051 | Level 1 | Level 1 | 13

# IfcWindow: 819mm x 759mm (12)
In: Level 2
Type - PredefinedType: WINDOW; ParameterTakesPrecedence: no
OverallHeight: 0.759 m; OverallWidth: 0.819 m
PSet_Revit_Type_Identity Data - Manufacturer: Manufacturer
PSet_Revit_Type_Other - AccessibilityPerformance: AccessibilityPerformance; CodePerformance: CodePerformance; ConfigurationType: ConfigurationType; ConstructionType: ConstructionType; FireRating: FireRating; GlazingAreaFraction: GlazingAreaFraction; OperationType: OperationType; Area: Area; Color: Color; Constituents: Constituents; Features: Features; Finish: Finish; Grade: Grade; Material: Material; ModelReference: ModelReference; NominalHeight: NominalHeight; NominalLength: NominalLength; NominalWidth: NominalWidth; ProductionYear: ProductionYear; Reference: Reference; Shape: Shape; Size: Size; SustainabilityPerformance: SustainabilityPerformance; WarrantyDescription: WarrantyDescription; WarrantyDurationLabor: WarrantyDurationLabor; WarrantyDurationParts: WarrantyDurationParts; WarrantyGuarantorLabor: WarrantyGuarantorLabor; WarrantyGuarantorParts: WarrantyGuarantorParts; ExpectedLife: ExpectedLife; ReplacementCost: ReplacementCost; AssetAccountingType: FIXED; ModelLabel: ModelLabel
PSet_Revit_Type_Materials and Finishes - Glass Pane Material: Glass; Sash: Sash
PSet_Revit_Type_Dimensions - Height: 0.759 m; Width: 0.819 m; Window Inset: 0.019 m
PSet_Revit_Type_Construction - Wall Closure: 0; Construction Type: Construction Type
PSet_Revit_Constraints - Level: Level 2
PSet_Revit_Other - InstallationDate: InstallationDate; SerialNumber: SerialNumber; WarrantyStartDate: WarrantyStartDate; BarCode: BarCode; AssetIdentifier: AssetIdentifier; TagNumber: TagNumber
PSet_Revit_Phasing - Phase Created: New Construction
Pset_WindowCommon - IsExternal: yes; FireRating: FireRating
Name | Type Mark | OmniClass Number | OmniClass Title | Frame Exterior Material = Frame Interior Material | Default Sill Height (m) | Sill Height (m) | Head Height (m) | Mark | Reference
M_Fixed:819mm x 759mm:819mm x 759mm:147994 | 02 | 23.30.20.17.11 | Fixed Windows | Sash | 0.1 | 0.1 | 0.859 | 15 | M_Fixed:819mm x 759mm
M_Fixed:819mm x 759mm:819mm x 759mm:180864 | 02 | 23.30.20.17.11 | Fixed Windows | Sash | 0.1 | 0.1 | 0.859 | 24 | M_Fixed:819mm x 759mm
M_Fixed:819mm x 759mm:819mm x 759mm:181583 | 02 | 23.30.20.17.11 | Fixed Windows | Sash | 0.1 | 0.1 | 0.859 | 29 | M_Fixed:819mm x 759mm
M_Fixed:819mm x 759mm:819mm x 759mm:149537 | 02 | 23.30.20.17.11 | Fixed Windows | Sash | 0.1 | 0.1 | 0.859 | 19 | M_Fixed:819mm x 759mm
M_Fixed:819mm x 759mm:819mm x 759mm:148722 | 02 | 23.30.20.17.11 | Fixed Windows | Sash | 0.1 | 1.751 | 2.51 | 17 | M_Fixed:819mm x 759mm
M_Fixed:819mm x 759mm:819mm x 759mm:149924 | 02 | 23.30.20.17.11 | Fixed Windows | Sash | 0.1 | 1.751 | 2.51 | 21 | M_Fixed:819mm x 759mm
M_Fixed:819mm x 759mm:819mm x 759mm:180663 | 02 | 23.30.20.17.11 | Fixed Windows | Sash | 0.1 | 1.751 | 2.51 | 23 | M_Fixed:819mm x 759mm
M_Fixed:819mm x 759mm:819mm x 759mm:181285 | 02 | 23.30.20.17.11 | Fixed Windows | Sash | 0.1 | 1.751 | 2.51 | 27 | M_Fixed:819mm x 759mm
M_Casement:819mm x 759mm:819mm x 759mm:148607 | 03 | 23.30.20.17.21.14 | Casement Windows |  | 0.915 | 0.9255 | 1.6845 | 16 | M_Casement:819mm x 759mm | PSet_Revit_Type_Materials and Finishes - Trim Exterior Material: Trim; Trim Interior Material: Trim
M_Casement:819mm x 759mm:819mm x 759mm:149736 | 03 | 23.30.20.17.21.14 | Casement Windows |  | 0.915 | 0.9255 | 1.6845 | 20 | M_Casement:819mm x 759mm | PSet_Revit_Type_Materials and Finishes - Trim Exterior Material: Trim; Trim Interior Material: Trim
M_Casement:819mm x 759mm:819mm x 759mm:180994 | 03 | 23.30.20.17.21.14 | Casement Windows |  | 0.915 | 0.9255 | 1.6845 | 25 | M_Casement:819mm x 759mm | PSet_Revit_Type_Materials and Finishes - Trim Exterior Material: Trim; Trim Interior Material: Trim
M_Casement:819mm x 759mm:819mm x 759mm:181548 | 03 | 23.30.20.17.21.14 | Casement Windows |  | 0.915 | 0.9255 | 1.6845 | 28 | M_Casement:819mm x 759mm | PSet_Revit_Type_Materials and Finishes - Trim Exterior Material: Trim; Trim Interior Material: Trim
